VERSION 5.7 ;
BUSBITCHARS "[]" ;
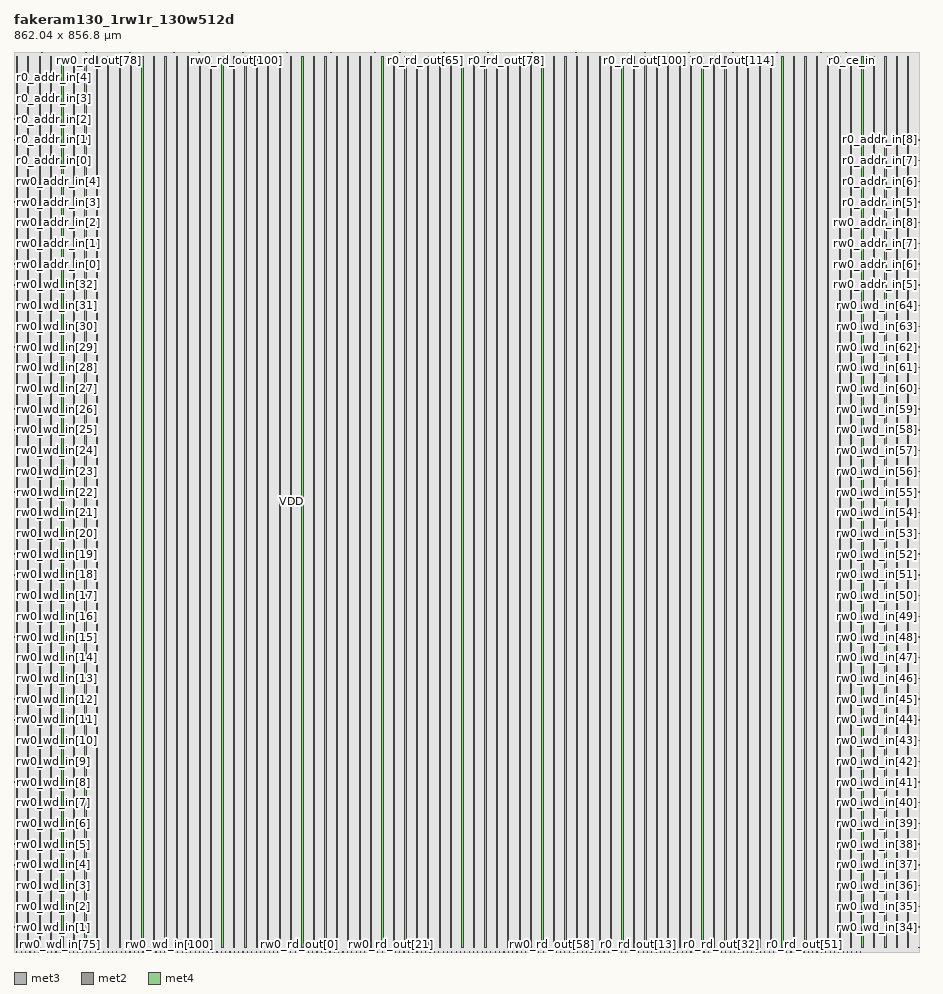
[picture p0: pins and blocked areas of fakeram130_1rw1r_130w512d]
MACRO fakeram130_1rw1r_130w512d
  FOREIGN fakeram130_1rw1r_130w512d 0 0 ;
  SYMMETRY X Y R90 ;
  SIZE 862.040 BY 856.800 ;
  CLASS BLOCK ;
  PIN rw0_wd_in[0]
    DIRECTION INPUT ;
    USE SIGNAL ;
    SHAPE ABUTMENT ;
    PORT
      LAYER met3 ;
      RECT 0.000 3.930 0.900 4.230 ;
    END
  END rw0_wd_in[0]
  PIN rw0_wd_in[1]
    DIRECTION INPUT ;
    USE SIGNAL ;
    SHAPE ABUTMENT ;
    PORT
      LAYER met3 ;
      RECT 0.000 23.650 0.900 23.950 ;
    END
  END rw0_wd_in[1]
  PIN rw0_wd_in[2]
    DIRECTION INPUT ;
    USE SIGNAL ;
    SHAPE ABUTMENT ;
    PORT
      LAYER met3 ;
      RECT 0.000 43.370 0.900 43.670 ;
    END
  END rw0_wd_in[2]
  PIN rw0_wd_in[3]
    DIRECTION INPUT ;
    USE SIGNAL ;
    SHAPE ABUTMENT ;
    PORT
      LAYER met3 ;
      RECT 0.000 63.090 0.900 63.390 ;
    END
  END rw0_wd_in[3]
  PIN rw0_wd_in[4]
    DIRECTION INPUT ;
    USE SIGNAL ;
    SHAPE ABUTMENT ;
    PORT
      LAYER met3 ;
      RECT 0.000 82.810 0.900 83.110 ;
    END
  END rw0_wd_in[4]
  PIN rw0_wd_in[5]
    DIRECTION INPUT ;
    USE SIGNAL ;
    SHAPE ABUTMENT ;
    PORT
      LAYER met3 ;
      RECT 0.000 102.530 0.900 102.830 ;
    END
  END rw0_wd_in[5]
  PIN rw0_wd_in[6]
    DIRECTION INPUT ;
    USE SIGNAL ;
    SHAPE ABUTMENT ;
    PORT
      LAYER met3 ;
      RECT 0.000 122.250 0.900 122.550 ;
    END
  END rw0_wd_in[6]
  PIN rw0_wd_in[7]
    DIRECTION INPUT ;
    USE SIGNAL ;
    SHAPE ABUTMENT ;
    PORT
      LAYER met3 ;
      RECT 0.000 141.970 0.900 142.270 ;
    END
  END rw0_wd_in[7]
  PIN rw0_wd_in[8]
    DIRECTION INPUT ;
    USE SIGNAL ;
    SHAPE ABUTMENT ;
    PORT
      LAYER met3 ;
      RECT 0.000 161.690 0.900 161.990 ;
    END
  END rw0_wd_in[8]
  PIN rw0_wd_in[9]
    DIRECTION INPUT ;
    USE SIGNAL ;
    SHAPE ABUTMENT ;
    PORT
      LAYER met3 ;
      RECT 0.000 181.410 0.900 181.710 ;
    END
  END rw0_wd_in[9]
  PIN rw0_wd_in[10]
    DIRECTION INPUT ;
    USE SIGNAL ;
    SHAPE ABUTMENT ;
    PORT
      LAYER met3 ;
      RECT 0.000 201.130 0.900 201.430 ;
    END
  END rw0_wd_in[10]
  PIN rw0_wd_in[11]
    DIRECTION INPUT ;
    USE SIGNAL ;
    SHAPE ABUTMENT ;
    PORT
      LAYER met3 ;
      RECT 0.000 220.850 0.900 221.150 ;
    END
  END rw0_wd_in[11]
  PIN rw0_wd_in[12]
    DIRECTION INPUT ;
    USE SIGNAL ;
    SHAPE ABUTMENT ;
    PORT
      LAYER met3 ;
      RECT 0.000 240.570 0.900 240.870 ;
    END
  END rw0_wd_in[12]
  PIN rw0_wd_in[13]
    DIRECTION INPUT ;
    USE SIGNAL ;
    SHAPE ABUTMENT ;
    PORT
      LAYER met3 ;
      RECT 0.000 260.290 0.900 260.590 ;
    END
  END rw0_wd_in[13]
  PIN rw0_wd_in[14]
    DIRECTION INPUT ;
    USE SIGNAL ;
    SHAPE ABUTMENT ;
    PORT
      LAYER met3 ;
      RECT 0.000 280.010 0.900 280.310 ;
    END
  END rw0_wd_in[14]
  PIN rw0_wd_in[15]
    DIRECTION INPUT ;
    USE SIGNAL ;
    SHAPE ABUTMENT ;
    PORT
      LAYER met3 ;
      RECT 0.000 299.730 0.900 300.030 ;
    END
  END rw0_wd_in[15]
  PIN rw0_wd_in[16]
    DIRECTION INPUT ;
    USE SIGNAL ;
    SHAPE ABUTMENT ;
    PORT
      LAYER met3 ;
      RECT 0.000 319.450 0.900 319.750 ;
    END
  END rw0_wd_in[16]
  PIN rw0_wd_in[17]
    DIRECTION INPUT ;
    USE SIGNAL ;
    SHAPE ABUTMENT ;
    PORT
      LAYER met3 ;
      RECT 0.000 339.170 0.900 339.470 ;
    END
  END rw0_wd_in[17]
  PIN rw0_wd_in[18]
    DIRECTION INPUT ;
    USE SIGNAL ;
    SHAPE ABUTMENT ;
    PORT
      LAYER met3 ;
      RECT 0.000 358.890 0.900 359.190 ;
    END
  END rw0_wd_in[18]
  PIN rw0_wd_in[19]
    DIRECTION INPUT ;
    USE SIGNAL ;
    SHAPE ABUTMENT ;
    PORT
      LAYER met3 ;
      RECT 0.000 378.610 0.900 378.910 ;
    END
  END rw0_wd_in[19]
  PIN rw0_wd_in[20]
    DIRECTION INPUT ;
    USE SIGNAL ;
    SHAPE ABUTMENT ;
    PORT
      LAYER met3 ;
      RECT 0.000 398.330 0.900 398.630 ;
    END
  END rw0_wd_in[20]
  PIN rw0_wd_in[21]
    DIRECTION INPUT ;
    USE SIGNAL ;
    SHAPE ABUTMENT ;
    PORT
      LAYER met3 ;
      RECT 0.000 418.050 0.900 418.350 ;
    END
  END rw0_wd_in[21]
  PIN rw0_wd_in[22]
    DIRECTION INPUT ;
    USE SIGNAL ;
    SHAPE ABUTMENT ;
    PORT
      LAYER met3 ;
      RECT 0.000 437.770 0.900 438.070 ;
    END
  END rw0_wd_in[22]
  PIN rw0_wd_in[23]
    DIRECTION INPUT ;
    USE SIGNAL ;
    SHAPE ABUTMENT ;
    PORT
      LAYER met3 ;
      RECT 0.000 457.490 0.900 457.790 ;
    END
  END rw0_wd_in[23]
  PIN rw0_wd_in[24]
    DIRECTION INPUT ;
    USE SIGNAL ;
    SHAPE ABUTMENT ;
    PORT
      LAYER met3 ;
      RECT 0.000 477.210 0.900 477.510 ;
    END
  END rw0_wd_in[24]
  PIN rw0_wd_in[25]
    DIRECTION INPUT ;
    USE SIGNAL ;
    SHAPE ABUTMENT ;
    PORT
      LAYER met3 ;
      RECT 0.000 496.930 0.900 497.230 ;
    END
  END rw0_wd_in[25]
  PIN rw0_wd_in[26]
    DIRECTION INPUT ;
    USE SIGNAL ;
    SHAPE ABUTMENT ;
    PORT
      LAYER met3 ;
      RECT 0.000 516.650 0.900 516.950 ;
    END
  END rw0_wd_in[26]
  PIN rw0_wd_in[27]
    DIRECTION INPUT ;
    USE SIGNAL ;
    SHAPE ABUTMENT ;
    PORT
      LAYER met3 ;
      RECT 0.000 536.370 0.900 536.670 ;
    END
  END rw0_wd_in[27]
  PIN rw0_wd_in[28]
    DIRECTION INPUT ;
    USE SIGNAL ;
    SHAPE ABUTMENT ;
    PORT
      LAYER met3 ;
      RECT 0.000 556.090 0.900 556.390 ;
    END
  END rw0_wd_in[28]
  PIN rw0_wd_in[29]
    DIRECTION INPUT ;
    USE SIGNAL ;
    SHAPE ABUTMENT ;
    PORT
      LAYER met3 ;
      RECT 0.000 575.810 0.900 576.110 ;
    END
  END rw0_wd_in[29]
  PIN rw0_wd_in[30]
    DIRECTION INPUT ;
    USE SIGNAL ;
    SHAPE ABUTMENT ;
    PORT
      LAYER met3 ;
      RECT 0.000 595.530 0.900 595.830 ;
    END
  END rw0_wd_in[30]
  PIN rw0_wd_in[31]
    DIRECTION INPUT ;
    USE SIGNAL ;
    SHAPE ABUTMENT ;
    PORT
      LAYER met3 ;
      RECT 0.000 615.250 0.900 615.550 ;
    END
  END rw0_wd_in[31]
  PIN rw0_wd_in[32]
    DIRECTION INPUT ;
    USE SIGNAL ;
    SHAPE ABUTMENT ;
    PORT
      LAYER met3 ;
      RECT 0.000 634.970 0.900 635.270 ;
    END
  END rw0_wd_in[32]
  PIN rw0_wd_in[33]
    DIRECTION INPUT ;
    USE SIGNAL ;
    SHAPE ABUTMENT ;
    PORT
      LAYER met3 ;
      RECT 861.140 3.930 862.040 4.230 ;
    END
  END rw0_wd_in[33]
  PIN rw0_wd_in[34]
    DIRECTION INPUT ;
    USE SIGNAL ;
    SHAPE ABUTMENT ;
    PORT
      LAYER met3 ;
      RECT 861.140 23.650 862.040 23.950 ;
    END
  END rw0_wd_in[34]
  PIN rw0_wd_in[35]
    DIRECTION INPUT ;
    USE SIGNAL ;
    SHAPE ABUTMENT ;
    PORT
      LAYER met3 ;
      RECT 861.140 43.370 862.040 43.670 ;
    END
  END rw0_wd_in[35]
  PIN rw0_wd_in[36]
    DIRECTION INPUT ;
    USE SIGNAL ;
    SHAPE ABUTMENT ;
    PORT
      LAYER met3 ;
      RECT 861.140 63.090 862.040 63.390 ;
    END
  END rw0_wd_in[36]
  PIN rw0_wd_in[37]
    DIRECTION INPUT ;
    USE SIGNAL ;
    SHAPE ABUTMENT ;
    PORT
      LAYER met3 ;
      RECT 861.140 82.810 862.040 83.110 ;
    END
  END rw0_wd_in[37]
  PIN rw0_wd_in[38]
    DIRECTION INPUT ;
    USE SIGNAL ;
    SHAPE ABUTMENT ;
    PORT
      LAYER met3 ;
      RECT 861.140 102.530 862.040 102.830 ;
    END
  END rw0_wd_in[38]
  PIN rw0_wd_in[39]
    DIRECTION INPUT ;
    USE SIGNAL ;
    SHAPE ABUTMENT ;
    PORT
      LAYER met3 ;
      RECT 861.140 122.250 862.040 122.550 ;
    END
  END rw0_wd_in[39]
  PIN rw0_wd_in[40]
    DIRECTION INPUT ;
    USE SIGNAL ;
    SHAPE ABUTMENT ;
    PORT
      LAYER met3 ;
      RECT 861.140 141.970 862.040 142.270 ;
    END
  END rw0_wd_in[40]
  PIN rw0_wd_in[41]
    DIRECTION INPUT ;
    USE SIGNAL ;
    SHAPE ABUTMENT ;
    PORT
      LAYER met3 ;
      RECT 861.140 161.690 862.040 161.990 ;
    END
  END rw0_wd_in[41]
  PIN rw0_wd_in[42]
    DIRECTION INPUT ;
    USE SIGNAL ;
    SHAPE ABUTMENT ;
    PORT
      LAYER met3 ;
      RECT 861.140 181.410 862.040 181.710 ;
    END
  END rw0_wd_in[42]
  PIN rw0_wd_in[43]
    DIRECTION INPUT ;
    USE SIGNAL ;
    SHAPE ABUTMENT ;
    PORT
      LAYER met3 ;
      RECT 861.140 201.130 862.040 201.430 ;
    END
  END rw0_wd_in[43]
  PIN rw0_wd_in[44]
    DIRECTION INPUT ;
    USE SIGNAL ;
    SHAPE ABUTMENT ;
    PORT
      LAYER met3 ;
      RECT 861.140 220.850 862.040 221.150 ;
    END
  END rw0_wd_in[44]
  PIN rw0_wd_in[45]
    DIRECTION INPUT ;
    USE SIGNAL ;
    SHAPE ABUTMENT ;
    PORT
      LAYER met3 ;
      RECT 861.140 240.570 862.040 240.870 ;
    END
  END rw0_wd_in[45]
  PIN rw0_wd_in[46]
    DIRECTION INPUT ;
    USE SIGNAL ;
    SHAPE ABUTMENT ;
    PORT
      LAYER met3 ;
      RECT 861.140 260.290 862.040 260.590 ;
    END
  END rw0_wd_in[46]
  PIN rw0_wd_in[47]
    DIRECTION INPUT ;
    USE SIGNAL ;
    SHAPE ABUTMENT ;
    PORT
      LAYER met3 ;
      RECT 861.140 280.010 862.040 280.310 ;
    END
  END rw0_wd_in[47]
  PIN rw0_wd_in[48]
    DIRECTION INPUT ;
    USE SIGNAL ;
    SHAPE ABUTMENT ;
    PORT
      LAYER met3 ;
      RECT 861.140 299.730 862.040 300.030 ;
    END
  END rw0_wd_in[48]
  PIN rw0_wd_in[49]
    DIRECTION INPUT ;
    USE SIGNAL ;
    SHAPE ABUTMENT ;
    PORT
      LAYER met3 ;
      RECT 861.140 319.450 862.040 319.750 ;
    END
  END rw0_wd_in[49]
  PIN rw0_wd_in[50]
    DIRECTION INPUT ;
    USE SIGNAL ;
    SHAPE ABUTMENT ;
    PORT
      LAYER met3 ;
      RECT 861.140 339.170 862.040 339.470 ;
    END
  END rw0_wd_in[50]
  PIN rw0_wd_in[51]
    DIRECTION INPUT ;
    USE SIGNAL ;
    SHAPE ABUTMENT ;
    PORT
      LAYER met3 ;
      RECT 861.140 358.890 862.040 359.190 ;
    END
  END rw0_wd_in[51]
  PIN rw0_wd_in[52]
    DIRECTION INPUT ;
    USE SIGNAL ;
    SHAPE ABUTMENT ;
    PORT
      LAYER met3 ;
      RECT 861.140 378.610 862.040 378.910 ;
    END
  END rw0_wd_in[52]
  PIN rw0_wd_in[53]
    DIRECTION INPUT ;
    USE SIGNAL ;
    SHAPE ABUTMENT ;
    PORT
      LAYER met3 ;
      RECT 861.140 398.330 862.040 398.630 ;
    END
  END rw0_wd_in[53]
  PIN rw0_wd_in[54]
    DIRECTION INPUT ;
    USE SIGNAL ;
    SHAPE ABUTMENT ;
    PORT
      LAYER met3 ;
      RECT 861.140 418.050 862.040 418.350 ;
    END
  END rw0_wd_in[54]
  PIN rw0_wd_in[55]
    DIRECTION INPUT ;
    USE SIGNAL ;
    SHAPE ABUTMENT ;
    PORT
      LAYER met3 ;
      RECT 861.140 437.770 862.040 438.070 ;
    END
  END rw0_wd_in[55]
  PIN rw0_wd_in[56]
    DIRECTION INPUT ;
    USE SIGNAL ;
    SHAPE ABUTMENT ;
    PORT
      LAYER met3 ;
      RECT 861.140 457.490 862.040 457.790 ;
    END
  END rw0_wd_in[56]
  PIN rw0_wd_in[57]
    DIRECTION INPUT ;
    USE SIGNAL ;
    SHAPE ABUTMENT ;
    PORT
      LAYER met3 ;
      RECT 861.140 477.210 862.040 477.510 ;
    END
  END rw0_wd_in[57]
  PIN rw0_wd_in[58]
    DIRECTION INPUT ;
    USE SIGNAL ;
    SHAPE ABUTMENT ;
    PORT
      LAYER met3 ;
      RECT 861.140 496.930 862.040 497.230 ;
    END
  END rw0_wd_in[58]
  PIN rw0_wd_in[59]
    DIRECTION INPUT ;
    USE SIGNAL ;
    SHAPE ABUTMENT ;
    PORT
      LAYER met3 ;
      RECT 861.140 516.650 862.040 516.950 ;
    END
  END rw0_wd_in[59]
  PIN rw0_wd_in[60]
    DIRECTION INPUT ;
    USE SIGNAL ;
    SHAPE ABUTMENT ;
    PORT
      LAYER met3 ;
      RECT 861.140 536.370 862.040 536.670 ;
    END
  END rw0_wd_in[60]
  PIN rw0_wd_in[61]
    DIRECTION INPUT ;
    USE SIGNAL ;
    SHAPE ABUTMENT ;
    PORT
      LAYER met3 ;
      RECT 861.140 556.090 862.040 556.390 ;
    END
  END rw0_wd_in[61]
  PIN rw0_wd_in[62]
    DIRECTION INPUT ;
    USE SIGNAL ;
    SHAPE ABUTMENT ;
    PORT
      LAYER met3 ;
      RECT 861.140 575.810 862.040 576.110 ;
    END
  END rw0_wd_in[62]
  PIN rw0_wd_in[63]
    DIRECTION INPUT ;
    USE SIGNAL ;
    SHAPE ABUTMENT ;
    PORT
      LAYER met3 ;
      RECT 861.140 595.530 862.040 595.830 ;
    END
  END rw0_wd_in[63]
  PIN rw0_wd_in[64]
    DIRECTION INPUT ;
    USE SIGNAL ;
    SHAPE ABUTMENT ;
    PORT
      LAYER met3 ;
      RECT 861.140 615.250 862.040 615.550 ;
    END
  END rw0_wd_in[64]
  PIN rw0_wd_in[65]
    DIRECTION OUTPUT ;
    USE SIGNAL ;
    SHAPE ABUTMENT ;
    PORT
      LAYER met2 ;
      RECT 2.690 0.000 2.830 0.420 ;
    END
  END rw0_wd_in[65]
  PIN rw0_wd_in[66]
    DIRECTION OUTPUT ;
    USE SIGNAL ;
    SHAPE ABUTMENT ;
    PORT
      LAYER met2 ;
      RECT 6.830 0.000 6.970 0.420 ;
    END
  END rw0_wd_in[66]
  PIN rw0_wd_in[67]
    DIRECTION OUTPUT ;
    USE SIGNAL ;
    SHAPE ABUTMENT ;
    PORT
      LAYER met2 ;
      RECT 10.970 0.000 11.110 0.420 ;
    END
  END rw0_wd_in[67]
  PIN rw0_wd_in[68]
    DIRECTION OUTPUT ;
    USE SIGNAL ;
    SHAPE ABUTMENT ;
    PORT
      LAYER met2 ;
      RECT 15.110 0.000 15.250 0.420 ;
    END
  END rw0_wd_in[68]
  PIN rw0_wd_in[69]
    DIRECTION OUTPUT ;
    USE SIGNAL ;
    SHAPE ABUTMENT ;
    PORT
      LAYER met2 ;
      RECT 19.250 0.000 19.390 0.420 ;
    END
  END rw0_wd_in[69]
  PIN rw0_wd_in[70]
    DIRECTION OUTPUT ;
    USE SIGNAL ;
    SHAPE ABUTMENT ;
    PORT
      LAYER met2 ;
      RECT 23.390 0.000 23.530 0.420 ;
    END
  END rw0_wd_in[70]
  PIN rw0_wd_in[71]
    DIRECTION OUTPUT ;
    USE SIGNAL ;
    SHAPE ABUTMENT ;
    PORT
      LAYER met2 ;
      RECT 27.530 0.000 27.670 0.420 ;
    END
  END rw0_wd_in[71]
  PIN rw0_wd_in[72]
    DIRECTION OUTPUT ;
    USE SIGNAL ;
    SHAPE ABUTMENT ;
    PORT
      LAYER met2 ;
      RECT 31.670 0.000 31.810 0.420 ;
    END
  END rw0_wd_in[72]
  PIN rw0_wd_in[73]
    DIRECTION OUTPUT ;
    USE SIGNAL ;
    SHAPE ABUTMENT ;
    PORT
      LAYER met2 ;
      RECT 35.810 0.000 35.950 0.420 ;
    END
  END rw0_wd_in[73]
  PIN rw0_wd_in[74]
    DIRECTION OUTPUT ;
    USE SIGNAL ;
    SHAPE ABUTMENT ;
    PORT
      LAYER met2 ;
      RECT 39.950 0.000 40.090 0.420 ;
    END
  END rw0_wd_in[74]
  PIN rw0_wd_in[75]
    DIRECTION OUTPUT ;
    USE SIGNAL ;
    SHAPE ABUTMENT ;
    PORT
      LAYER met2 ;
      RECT 44.090 0.000 44.230 0.420 ;
    END
  END rw0_wd_in[75]
  PIN rw0_wd_in[76]
    DIRECTION OUTPUT ;
    USE SIGNAL ;
    SHAPE ABUTMENT ;
    PORT
      LAYER met2 ;
      RECT 48.230 0.000 48.370 0.420 ;
    END
  END rw0_wd_in[76]
  PIN rw0_wd_in[77]
    DIRECTION OUTPUT ;
    USE SIGNAL ;
    SHAPE ABUTMENT ;
    PORT
      LAYER met2 ;
      RECT 52.370 0.000 52.510 0.420 ;
    END
  END rw0_wd_in[77]
  PIN rw0_wd_in[78]
    DIRECTION OUTPUT ;
    USE SIGNAL ;
    SHAPE ABUTMENT ;
    PORT
      LAYER met2 ;
      RECT 56.510 0.000 56.650 0.420 ;
    END
  END rw0_wd_in[78]
  PIN rw0_wd_in[79]
    DIRECTION OUTPUT ;
    USE SIGNAL ;
    SHAPE ABUTMENT ;
    PORT
      LAYER met2 ;
      RECT 60.650 0.000 60.790 0.420 ;
    END
  END rw0_wd_in[79]
  PIN rw0_wd_in[80]
    DIRECTION OUTPUT ;
    USE SIGNAL ;
    SHAPE ABUTMENT ;
    PORT
      LAYER met2 ;
      RECT 64.790 0.000 64.930 0.420 ;
    END
  END rw0_wd_in[80]
  PIN rw0_wd_in[81]
    DIRECTION OUTPUT ;
    USE SIGNAL ;
    SHAPE ABUTMENT ;
    PORT
      LAYER met2 ;
      RECT 68.930 0.000 69.070 0.420 ;
    END
  END rw0_wd_in[81]
  PIN rw0_wd_in[82]
    DIRECTION OUTPUT ;
    USE SIGNAL ;
    SHAPE ABUTMENT ;
    PORT
      LAYER met2 ;
      RECT 73.070 0.000 73.210 0.420 ;
    END
  END rw0_wd_in[82]
  PIN rw0_wd_in[83]
    DIRECTION OUTPUT ;
    USE SIGNAL ;
    SHAPE ABUTMENT ;
    PORT
      LAYER met2 ;
      RECT 77.210 0.000 77.350 0.420 ;
    END
  END rw0_wd_in[83]
  PIN rw0_wd_in[84]
    DIRECTION OUTPUT ;
    USE SIGNAL ;
    SHAPE ABUTMENT ;
    PORT
      LAYER met2 ;
      RECT 81.350 0.000 81.490 0.420 ;
    END
  END rw0_wd_in[84]
  PIN rw0_wd_in[85]
    DIRECTION OUTPUT ;
    USE SIGNAL ;
    SHAPE ABUTMENT ;
    PORT
      LAYER met2 ;
      RECT 85.490 0.000 85.630 0.420 ;
    END
  END rw0_wd_in[85]
  PIN rw0_wd_in[86]
    DIRECTION OUTPUT ;
    USE SIGNAL ;
    SHAPE ABUTMENT ;
    PORT
      LAYER met2 ;
      RECT 89.630 0.000 89.770 0.420 ;
    END
  END rw0_wd_in[86]
  PIN rw0_wd_in[87]
    DIRECTION OUTPUT ;
    USE SIGNAL ;
    SHAPE ABUTMENT ;
    PORT
      LAYER met2 ;
      RECT 93.770 0.000 93.910 0.420 ;
    END
  END rw0_wd_in[87]
  PIN rw0_wd_in[88]
    DIRECTION OUTPUT ;
    USE SIGNAL ;
    SHAPE ABUTMENT ;
    PORT
      LAYER met2 ;
      RECT 97.910 0.000 98.050 0.420 ;
    END
  END rw0_wd_in[88]
  PIN rw0_wd_in[89]
    DIRECTION OUTPUT ;
    USE SIGNAL ;
    SHAPE ABUTMENT ;
    PORT
      LAYER met2 ;
      RECT 102.050 0.000 102.190 0.420 ;
    END
  END rw0_wd_in[89]
  PIN rw0_wd_in[90]
    DIRECTION OUTPUT ;
    USE SIGNAL ;
    SHAPE ABUTMENT ;
    PORT
      LAYER met2 ;
      RECT 106.190 0.000 106.330 0.420 ;
    END
  END rw0_wd_in[90]
  PIN rw0_wd_in[91]
    DIRECTION OUTPUT ;
    USE SIGNAL ;
    SHAPE ABUTMENT ;
    PORT
      LAYER met2 ;
      RECT 110.330 0.000 110.470 0.420 ;
    END
  END rw0_wd_in[91]
  PIN rw0_wd_in[92]
    DIRECTION OUTPUT ;
    USE SIGNAL ;
    SHAPE ABUTMENT ;
    PORT
      LAYER met2 ;
      RECT 114.470 0.000 114.610 0.420 ;
    END
  END rw0_wd_in[92]
  PIN rw0_wd_in[93]
    DIRECTION OUTPUT ;
    USE SIGNAL ;
    SHAPE ABUTMENT ;
    PORT
      LAYER met2 ;
      RECT 118.610 0.000 118.750 0.420 ;
    END
  END rw0_wd_in[93]
  PIN rw0_wd_in[94]
    DIRECTION OUTPUT ;
    USE SIGNAL ;
    SHAPE ABUTMENT ;
    PORT
      LAYER met2 ;
      RECT 122.750 0.000 122.890 0.420 ;
    END
  END rw0_wd_in[94]
  PIN rw0_wd_in[95]
    DIRECTION OUTPUT ;
    USE SIGNAL ;
    SHAPE ABUTMENT ;
    PORT
      LAYER met2 ;
      RECT 126.890 0.000 127.030 0.420 ;
    END
  END rw0_wd_in[95]
  PIN rw0_wd_in[96]
    DIRECTION OUTPUT ;
    USE SIGNAL ;
    SHAPE ABUTMENT ;
    PORT
      LAYER met2 ;
      RECT 131.030 0.000 131.170 0.420 ;
    END
  END rw0_wd_in[96]
  PIN rw0_wd_in[97]
    DIRECTION OUTPUT ;
    USE SIGNAL ;
    SHAPE ABUTMENT ;
    PORT
      LAYER met2 ;
      RECT 135.170 0.000 135.310 0.420 ;
    END
  END rw0_wd_in[97]
  PIN rw0_wd_in[98]
    DIRECTION OUTPUT ;
    USE SIGNAL ;
    SHAPE ABUTMENT ;
    PORT
      LAYER met2 ;
      RECT 139.310 0.000 139.450 0.420 ;
    END
  END rw0_wd_in[98]
  PIN rw0_wd_in[99]
    DIRECTION OUTPUT ;
    USE SIGNAL ;
    SHAPE ABUTMENT ;
    PORT
      LAYER met2 ;
      RECT 143.450 0.000 143.590 0.420 ;
    END
  END rw0_wd_in[99]
  PIN rw0_wd_in[100]
    DIRECTION OUTPUT ;
    USE SIGNAL ;
    SHAPE ABUTMENT ;
    PORT
      LAYER met2 ;
      RECT 147.590 0.000 147.730 0.420 ;
    END
  END rw0_wd_in[100]
  PIN rw0_wd_in[101]
    DIRECTION OUTPUT ;
    USE SIGNAL ;
    SHAPE ABUTMENT ;
    PORT
      LAYER met2 ;
      RECT 151.730 0.000 151.870 0.420 ;
    END
  END rw0_wd_in[101]
  PIN rw0_wd_in[102]
    DIRECTION OUTPUT ;
    USE SIGNAL ;
    SHAPE ABUTMENT ;
    PORT
      LAYER met2 ;
      RECT 155.870 0.000 156.010 0.420 ;
    END
  END rw0_wd_in[102]
  PIN rw0_wd_in[103]
    DIRECTION OUTPUT ;
    USE SIGNAL ;
    SHAPE ABUTMENT ;
    PORT
      LAYER met2 ;
      RECT 160.010 0.000 160.150 0.420 ;
    END
  END rw0_wd_in[103]
  PIN rw0_wd_in[104]
    DIRECTION OUTPUT ;
    USE SIGNAL ;
    SHAPE ABUTMENT ;
    PORT
      LAYER met2 ;
      RECT 164.150 0.000 164.290 0.420 ;
    END
  END rw0_wd_in[104]
  PIN rw0_wd_in[105]
    DIRECTION OUTPUT ;
    USE SIGNAL ;
    SHAPE ABUTMENT ;
    PORT
      LAYER met2 ;
      RECT 168.290 0.000 168.430 0.420 ;
    END
  END rw0_wd_in[105]
  PIN rw0_wd_in[106]
    DIRECTION OUTPUT ;
    USE SIGNAL ;
    SHAPE ABUTMENT ;
    PORT
      LAYER met2 ;
      RECT 172.430 0.000 172.570 0.420 ;
    END
  END rw0_wd_in[106]
  PIN rw0_wd_in[107]
    DIRECTION OUTPUT ;
    USE SIGNAL ;
    SHAPE ABUTMENT ;
    PORT
      LAYER met2 ;
      RECT 176.570 0.000 176.710 0.420 ;
    END
  END rw0_wd_in[107]
  PIN rw0_wd_in[108]
    DIRECTION OUTPUT ;
    USE SIGNAL ;
    SHAPE ABUTMENT ;
    PORT
      LAYER met2 ;
      RECT 180.710 0.000 180.850 0.420 ;
    END
  END rw0_wd_in[108]
  PIN rw0_wd_in[109]
    DIRECTION OUTPUT ;
    USE SIGNAL ;
    SHAPE ABUTMENT ;
    PORT
      LAYER met2 ;
      RECT 184.850 0.000 184.990 0.420 ;
    END
  END rw0_wd_in[109]
  PIN rw0_wd_in[110]
    DIRECTION OUTPUT ;
    USE SIGNAL ;
    SHAPE ABUTMENT ;
    PORT
      LAYER met2 ;
      RECT 188.990 0.000 189.130 0.420 ;
    END
  END rw0_wd_in[110]
  PIN rw0_wd_in[111]
    DIRECTION OUTPUT ;
    USE SIGNAL ;
    SHAPE ABUTMENT ;
    PORT
      LAYER met2 ;
      RECT 193.130 0.000 193.270 0.420 ;
    END
  END rw0_wd_in[111]
  PIN rw0_wd_in[112]
    DIRECTION OUTPUT ;
    USE SIGNAL ;
    SHAPE ABUTMENT ;
    PORT
      LAYER met2 ;
      RECT 197.270 0.000 197.410 0.420 ;
    END
  END rw0_wd_in[112]
  PIN rw0_wd_in[113]
    DIRECTION OUTPUT ;
    USE SIGNAL ;
    SHAPE ABUTMENT ;
    PORT
      LAYER met2 ;
      RECT 201.410 0.000 201.550 0.420 ;
    END
  END rw0_wd_in[113]
  PIN rw0_wd_in[114]
    DIRECTION OUTPUT ;
    USE SIGNAL ;
    SHAPE ABUTMENT ;
    PORT
      LAYER met2 ;
      RECT 205.550 0.000 205.690 0.420 ;
    END
  END rw0_wd_in[114]
  PIN rw0_wd_in[115]
    DIRECTION OUTPUT ;
    USE SIGNAL ;
    SHAPE ABUTMENT ;
    PORT
      LAYER met2 ;
      RECT 209.690 0.000 209.830 0.420 ;
    END
  END rw0_wd_in[115]
  PIN rw0_wd_in[116]
    DIRECTION OUTPUT ;
    USE SIGNAL ;
    SHAPE ABUTMENT ;
    PORT
      LAYER met2 ;
      RECT 213.830 0.000 213.970 0.420 ;
    END
  END rw0_wd_in[116]
  PIN rw0_wd_in[117]
    DIRECTION OUTPUT ;
    USE SIGNAL ;
    SHAPE ABUTMENT ;
    PORT
      LAYER met2 ;
      RECT 217.970 0.000 218.110 0.420 ;
    END
  END rw0_wd_in[117]
  PIN rw0_wd_in[118]
    DIRECTION OUTPUT ;
    USE SIGNAL ;
    SHAPE ABUTMENT ;
    PORT
      LAYER met2 ;
      RECT 222.110 0.000 222.250 0.420 ;
    END
  END rw0_wd_in[118]
  PIN rw0_wd_in[119]
    DIRECTION OUTPUT ;
    USE SIGNAL ;
    SHAPE ABUTMENT ;
    PORT
      LAYER met2 ;
      RECT 226.250 0.000 226.390 0.420 ;
    END
  END rw0_wd_in[119]
  PIN rw0_wd_in[120]
    DIRECTION OUTPUT ;
    USE SIGNAL ;
    SHAPE ABUTMENT ;
    PORT
      LAYER met2 ;
      RECT 230.390 0.000 230.530 0.420 ;
    END
  END rw0_wd_in[120]
  PIN rw0_wd_in[121]
    DIRECTION OUTPUT ;
    USE SIGNAL ;
    SHAPE ABUTMENT ;
    PORT
      LAYER met2 ;
      RECT 234.530 0.000 234.670 0.420 ;
    END
  END rw0_wd_in[121]
  PIN rw0_wd_in[122]
    DIRECTION OUTPUT ;
    USE SIGNAL ;
    SHAPE ABUTMENT ;
    PORT
      LAYER met2 ;
      RECT 238.670 0.000 238.810 0.420 ;
    END
  END rw0_wd_in[122]
  PIN rw0_wd_in[123]
    DIRECTION OUTPUT ;
    USE SIGNAL ;
    SHAPE ABUTMENT ;
    PORT
      LAYER met2 ;
      RECT 242.810 0.000 242.950 0.420 ;
    END
  END rw0_wd_in[123]
  PIN rw0_wd_in[124]
    DIRECTION OUTPUT ;
    USE SIGNAL ;
    SHAPE ABUTMENT ;
    PORT
      LAYER met2 ;
      RECT 246.950 0.000 247.090 0.420 ;
    END
  END rw0_wd_in[124]
  PIN rw0_wd_in[125]
    DIRECTION OUTPUT ;
    USE SIGNAL ;
    SHAPE ABUTMENT ;
    PORT
      LAYER met2 ;
      RECT 251.090 0.000 251.230 0.420 ;
    END
  END rw0_wd_in[125]
  PIN rw0_wd_in[126]
    DIRECTION OUTPUT ;
    USE SIGNAL ;
    SHAPE ABUTMENT ;
    PORT
      LAYER met2 ;
      RECT 255.230 0.000 255.370 0.420 ;
    END
  END rw0_wd_in[126]
  PIN rw0_wd_in[127]
    DIRECTION OUTPUT ;
    USE SIGNAL ;
    SHAPE ABUTMENT ;
    PORT
      LAYER met2 ;
      RECT 259.370 0.000 259.510 0.420 ;
    END
  END rw0_wd_in[127]
  PIN rw0_wd_in[128]
    DIRECTION OUTPUT ;
    USE SIGNAL ;
    SHAPE ABUTMENT ;
    PORT
      LAYER met2 ;
      RECT 263.510 0.000 263.650 0.420 ;
    END
  END rw0_wd_in[128]
  PIN rw0_wd_in[129]
    DIRECTION OUTPUT ;
    USE SIGNAL ;
    SHAPE ABUTMENT ;
    PORT
      LAYER met2 ;
      RECT 267.650 0.000 267.790 0.420 ;
    END
  END rw0_wd_in[129]
  PIN rw0_rd_out[0]
    DIRECTION OUTPUT ;
    USE SIGNAL ;
    SHAPE ABUTMENT ;
    PORT
      LAYER met2 ;
      RECT 271.790 0.000 271.930 0.420 ;
    END
  END rw0_rd_out[0]
  PIN rw0_rd_out[1]
    DIRECTION OUTPUT ;
    USE SIGNAL ;
    SHAPE ABUTMENT ;
    PORT
      LAYER met2 ;
      RECT 275.930 0.000 276.070 0.420 ;
    END
  END rw0_rd_out[1]
  PIN rw0_rd_out[2]
    DIRECTION OUTPUT ;
    USE SIGNAL ;
    SHAPE ABUTMENT ;
    PORT
      LAYER met2 ;
      RECT 280.070 0.000 280.210 0.420 ;
    END
  END rw0_rd_out[2]
  PIN rw0_rd_out[3]
    DIRECTION OUTPUT ;
    USE SIGNAL ;
    SHAPE ABUTMENT ;
    PORT
      LAYER met2 ;
      RECT 284.210 0.000 284.350 0.420 ;
    END
  END rw0_rd_out[3]
  PIN rw0_rd_out[4]
    DIRECTION OUTPUT ;
    USE SIGNAL ;
    SHAPE ABUTMENT ;
    PORT
      LAYER met2 ;
      RECT 288.350 0.000 288.490 0.420 ;
    END
  END rw0_rd_out[4]
  PIN rw0_rd_out[5]
    DIRECTION OUTPUT ;
    USE SIGNAL ;
    SHAPE ABUTMENT ;
    PORT
      LAYER met2 ;
      RECT 292.490 0.000 292.630 0.420 ;
    END
  END rw0_rd_out[5]
  PIN rw0_rd_out[6]
    DIRECTION OUTPUT ;
    USE SIGNAL ;
    SHAPE ABUTMENT ;
    PORT
      LAYER met2 ;
      RECT 296.630 0.000 296.770 0.420 ;
    END
  END rw0_rd_out[6]
  PIN rw0_rd_out[7]
    DIRECTION OUTPUT ;
    USE SIGNAL ;
    SHAPE ABUTMENT ;
    PORT
      LAYER met2 ;
      RECT 300.770 0.000 300.910 0.420 ;
    END
  END rw0_rd_out[7]
  PIN rw0_rd_out[8]
    DIRECTION OUTPUT ;
    USE SIGNAL ;
    SHAPE ABUTMENT ;
    PORT
      LAYER met2 ;
      RECT 304.910 0.000 305.050 0.420 ;
    END
  END rw0_rd_out[8]
  PIN rw0_rd_out[9]
    DIRECTION OUTPUT ;
    USE SIGNAL ;
    SHAPE ABUTMENT ;
    PORT
      LAYER met2 ;
      RECT 309.050 0.000 309.190 0.420 ;
    END
  END rw0_rd_out[9]
  PIN rw0_rd_out[10]
    DIRECTION OUTPUT ;
    USE SIGNAL ;
    SHAPE ABUTMENT ;
    PORT
      LAYER met2 ;
      RECT 313.190 0.000 313.330 0.420 ;
    END
  END rw0_rd_out[10]
  PIN rw0_rd_out[11]
    DIRECTION OUTPUT ;
    USE SIGNAL ;
    SHAPE ABUTMENT ;
    PORT
      LAYER met2 ;
      RECT 317.330 0.000 317.470 0.420 ;
    END
  END rw0_rd_out[11]
  PIN rw0_rd_out[12]
    DIRECTION OUTPUT ;
    USE SIGNAL ;
    SHAPE ABUTMENT ;
    PORT
      LAYER met2 ;
      RECT 321.470 0.000 321.610 0.420 ;
    END
  END rw0_rd_out[12]
  PIN rw0_rd_out[13]
    DIRECTION OUTPUT ;
    USE SIGNAL ;
    SHAPE ABUTMENT ;
    PORT
      LAYER met2 ;
      RECT 325.610 0.000 325.750 0.420 ;
    END
  END rw0_rd_out[13]
  PIN rw0_rd_out[14]
    DIRECTION OUTPUT ;
    USE SIGNAL ;
    SHAPE ABUTMENT ;
    PORT
      LAYER met2 ;
      RECT 329.750 0.000 329.890 0.420 ;
    END
  END rw0_rd_out[14]
  PIN rw0_rd_out[15]
    DIRECTION OUTPUT ;
    USE SIGNAL ;
    SHAPE ABUTMENT ;
    PORT
      LAYER met2 ;
      RECT 333.890 0.000 334.030 0.420 ;
    END
  END rw0_rd_out[15]
  PIN rw0_rd_out[16]
    DIRECTION OUTPUT ;
    USE SIGNAL ;
    SHAPE ABUTMENT ;
    PORT
      LAYER met2 ;
      RECT 338.030 0.000 338.170 0.420 ;
    END
  END rw0_rd_out[16]
  PIN rw0_rd_out[17]
    DIRECTION OUTPUT ;
    USE SIGNAL ;
    SHAPE ABUTMENT ;
    PORT
      LAYER met2 ;
      RECT 342.170 0.000 342.310 0.420 ;
    END
  END rw0_rd_out[17]
  PIN rw0_rd_out[18]
    DIRECTION OUTPUT ;
    USE SIGNAL ;
    SHAPE ABUTMENT ;
    PORT
      LAYER met2 ;
      RECT 346.310 0.000 346.450 0.420 ;
    END
  END rw0_rd_out[18]
  PIN rw0_rd_out[19]
    DIRECTION OUTPUT ;
    USE SIGNAL ;
    SHAPE ABUTMENT ;
    PORT
      LAYER met2 ;
      RECT 350.450 0.000 350.590 0.420 ;
    END
  END rw0_rd_out[19]
  PIN rw0_rd_out[20]
    DIRECTION OUTPUT ;
    USE SIGNAL ;
    SHAPE ABUTMENT ;
    PORT
      LAYER met2 ;
      RECT 354.590 0.000 354.730 0.420 ;
    END
  END rw0_rd_out[20]
  PIN rw0_rd_out[21]
    DIRECTION OUTPUT ;
    USE SIGNAL ;
    SHAPE ABUTMENT ;
    PORT
      LAYER met2 ;
      RECT 358.730 0.000 358.870 0.420 ;
    END
  END rw0_rd_out[21]
  PIN rw0_rd_out[22]
    DIRECTION OUTPUT ;
    USE SIGNAL ;
    SHAPE ABUTMENT ;
    PORT
      LAYER met2 ;
      RECT 362.870 0.000 363.010 0.420 ;
    END
  END rw0_rd_out[22]
  PIN rw0_rd_out[23]
    DIRECTION OUTPUT ;
    USE SIGNAL ;
    SHAPE ABUTMENT ;
    PORT
      LAYER met2 ;
      RECT 367.010 0.000 367.150 0.420 ;
    END
  END rw0_rd_out[23]
  PIN rw0_rd_out[24]
    DIRECTION OUTPUT ;
    USE SIGNAL ;
    SHAPE ABUTMENT ;
    PORT
      LAYER met2 ;
      RECT 371.150 0.000 371.290 0.420 ;
    END
  END rw0_rd_out[24]
  PIN rw0_rd_out[25]
    DIRECTION OUTPUT ;
    USE SIGNAL ;
    SHAPE ABUTMENT ;
    PORT
      LAYER met2 ;
      RECT 375.290 0.000 375.430 0.420 ;
    END
  END rw0_rd_out[25]
  PIN rw0_rd_out[26]
    DIRECTION OUTPUT ;
    USE SIGNAL ;
    SHAPE ABUTMENT ;
    PORT
      LAYER met2 ;
      RECT 379.430 0.000 379.570 0.420 ;
    END
  END rw0_rd_out[26]
  PIN rw0_rd_out[27]
    DIRECTION OUTPUT ;
    USE SIGNAL ;
    SHAPE ABUTMENT ;
    PORT
      LAYER met2 ;
      RECT 383.570 0.000 383.710 0.420 ;
    END
  END rw0_rd_out[27]
  PIN rw0_rd_out[28]
    DIRECTION OUTPUT ;
    USE SIGNAL ;
    SHAPE ABUTMENT ;
    PORT
      LAYER met2 ;
      RECT 387.710 0.000 387.850 0.420 ;
    END
  END rw0_rd_out[28]
  PIN rw0_rd_out[29]
    DIRECTION OUTPUT ;
    USE SIGNAL ;
    SHAPE ABUTMENT ;
    PORT
      LAYER met2 ;
      RECT 391.850 0.000 391.990 0.420 ;
    END
  END rw0_rd_out[29]
  PIN rw0_rd_out[30]
    DIRECTION OUTPUT ;
    USE SIGNAL ;
    SHAPE ABUTMENT ;
    PORT
      LAYER met2 ;
      RECT 395.990 0.000 396.130 0.420 ;
    END
  END rw0_rd_out[30]
  PIN rw0_rd_out[31]
    DIRECTION OUTPUT ;
    USE SIGNAL ;
    SHAPE ABUTMENT ;
    PORT
      LAYER met2 ;
      RECT 400.130 0.000 400.270 0.420 ;
    END
  END rw0_rd_out[31]
  PIN rw0_rd_out[32]
    DIRECTION OUTPUT ;
    USE SIGNAL ;
    SHAPE ABUTMENT ;
    PORT
      LAYER met2 ;
      RECT 404.270 0.000 404.410 0.420 ;
    END
  END rw0_rd_out[32]
  PIN rw0_rd_out[33]
    DIRECTION OUTPUT ;
    USE SIGNAL ;
    SHAPE ABUTMENT ;
    PORT
      LAYER met2 ;
      RECT 408.410 0.000 408.550 0.420 ;
    END
  END rw0_rd_out[33]
  PIN rw0_rd_out[34]
    DIRECTION OUTPUT ;
    USE SIGNAL ;
    SHAPE ABUTMENT ;
    PORT
      LAYER met2 ;
      RECT 412.550 0.000 412.690 0.420 ;
    END
  END rw0_rd_out[34]
  PIN rw0_rd_out[35]
    DIRECTION OUTPUT ;
    USE SIGNAL ;
    SHAPE ABUTMENT ;
    PORT
      LAYER met2 ;
      RECT 416.690 0.000 416.830 0.420 ;
    END
  END rw0_rd_out[35]
  PIN rw0_rd_out[36]
    DIRECTION OUTPUT ;
    USE SIGNAL ;
    SHAPE ABUTMENT ;
    PORT
      LAYER met2 ;
      RECT 420.830 0.000 420.970 0.420 ;
    END
  END rw0_rd_out[36]
  PIN rw0_rd_out[37]
    DIRECTION OUTPUT ;
    USE SIGNAL ;
    SHAPE ABUTMENT ;
    PORT
      LAYER met2 ;
      RECT 424.970 0.000 425.110 0.420 ;
    END
  END rw0_rd_out[37]
  PIN rw0_rd_out[38]
    DIRECTION OUTPUT ;
    USE SIGNAL ;
    SHAPE ABUTMENT ;
    PORT
      LAYER met2 ;
      RECT 429.110 0.000 429.250 0.420 ;
    END
  END rw0_rd_out[38]
  PIN rw0_rd_out[39]
    DIRECTION OUTPUT ;
    USE SIGNAL ;
    SHAPE ABUTMENT ;
    PORT
      LAYER met2 ;
      RECT 433.250 0.000 433.390 0.420 ;
    END
  END rw0_rd_out[39]
  PIN rw0_rd_out[40]
    DIRECTION OUTPUT ;
    USE SIGNAL ;
    SHAPE ABUTMENT ;
    PORT
      LAYER met2 ;
      RECT 437.390 0.000 437.530 0.420 ;
    END
  END rw0_rd_out[40]
  PIN rw0_rd_out[41]
    DIRECTION OUTPUT ;
    USE SIGNAL ;
    SHAPE ABUTMENT ;
    PORT
      LAYER met2 ;
      RECT 441.530 0.000 441.670 0.420 ;
    END
  END rw0_rd_out[41]
  PIN rw0_rd_out[42]
    DIRECTION OUTPUT ;
    USE SIGNAL ;
    SHAPE ABUTMENT ;
    PORT
      LAYER met2 ;
      RECT 445.670 0.000 445.810 0.420 ;
    END
  END rw0_rd_out[42]
  PIN rw0_rd_out[43]
    DIRECTION OUTPUT ;
    USE SIGNAL ;
    SHAPE ABUTMENT ;
    PORT
      LAYER met2 ;
      RECT 449.810 0.000 449.950 0.420 ;
    END
  END rw0_rd_out[43]
  PIN rw0_rd_out[44]
    DIRECTION OUTPUT ;
    USE SIGNAL ;
    SHAPE ABUTMENT ;
    PORT
      LAYER met2 ;
      RECT 453.950 0.000 454.090 0.420 ;
    END
  END rw0_rd_out[44]
  PIN rw0_rd_out[45]
    DIRECTION OUTPUT ;
    USE SIGNAL ;
    SHAPE ABUTMENT ;
    PORT
      LAYER met2 ;
      RECT 458.090 0.000 458.230 0.420 ;
    END
  END rw0_rd_out[45]
  PIN rw0_rd_out[46]
    DIRECTION OUTPUT ;
    USE SIGNAL ;
    SHAPE ABUTMENT ;
    PORT
      LAYER met2 ;
      RECT 462.230 0.000 462.370 0.420 ;
    END
  END rw0_rd_out[46]
  PIN rw0_rd_out[47]
    DIRECTION OUTPUT ;
    USE SIGNAL ;
    SHAPE ABUTMENT ;
    PORT
      LAYER met2 ;
      RECT 466.370 0.000 466.510 0.420 ;
    END
  END rw0_rd_out[47]
  PIN rw0_rd_out[48]
    DIRECTION OUTPUT ;
    USE SIGNAL ;
    SHAPE ABUTMENT ;
    PORT
      LAYER met2 ;
      RECT 470.510 0.000 470.650 0.420 ;
    END
  END rw0_rd_out[48]
  PIN rw0_rd_out[49]
    DIRECTION OUTPUT ;
    USE SIGNAL ;
    SHAPE ABUTMENT ;
    PORT
      LAYER met2 ;
      RECT 474.650 0.000 474.790 0.420 ;
    END
  END rw0_rd_out[49]
  PIN rw0_rd_out[50]
    DIRECTION OUTPUT ;
    USE SIGNAL ;
    SHAPE ABUTMENT ;
    PORT
      LAYER met2 ;
      RECT 478.790 0.000 478.930 0.420 ;
    END
  END rw0_rd_out[50]
  PIN rw0_rd_out[51]
    DIRECTION OUTPUT ;
    USE SIGNAL ;
    SHAPE ABUTMENT ;
    PORT
      LAYER met2 ;
      RECT 482.930 0.000 483.070 0.420 ;
    END
  END rw0_rd_out[51]
  PIN rw0_rd_out[52]
    DIRECTION OUTPUT ;
    USE SIGNAL ;
    SHAPE ABUTMENT ;
    PORT
      LAYER met2 ;
      RECT 487.070 0.000 487.210 0.420 ;
    END
  END rw0_rd_out[52]
  PIN rw0_rd_out[53]
    DIRECTION OUTPUT ;
    USE SIGNAL ;
    SHAPE ABUTMENT ;
    PORT
      LAYER met2 ;
      RECT 491.210 0.000 491.350 0.420 ;
    END
  END rw0_rd_out[53]
  PIN rw0_rd_out[54]
    DIRECTION OUTPUT ;
    USE SIGNAL ;
    SHAPE ABUTMENT ;
    PORT
      LAYER met2 ;
      RECT 495.350 0.000 495.490 0.420 ;
    END
  END rw0_rd_out[54]
  PIN rw0_rd_out[55]
    DIRECTION OUTPUT ;
    USE SIGNAL ;
    SHAPE ABUTMENT ;
    PORT
      LAYER met2 ;
      RECT 499.490 0.000 499.630 0.420 ;
    END
  END rw0_rd_out[55]
  PIN rw0_rd_out[56]
    DIRECTION OUTPUT ;
    USE SIGNAL ;
    SHAPE ABUTMENT ;
    PORT
      LAYER met2 ;
      RECT 503.630 0.000 503.770 0.420 ;
    END
  END rw0_rd_out[56]
  PIN rw0_rd_out[57]
    DIRECTION OUTPUT ;
    USE SIGNAL ;
    SHAPE ABUTMENT ;
    PORT
      LAYER met2 ;
      RECT 507.770 0.000 507.910 0.420 ;
    END
  END rw0_rd_out[57]
  PIN rw0_rd_out[58]
    DIRECTION OUTPUT ;
    USE SIGNAL ;
    SHAPE ABUTMENT ;
    PORT
      LAYER met2 ;
      RECT 511.910 0.000 512.050 0.420 ;
    END
  END rw0_rd_out[58]
  PIN rw0_rd_out[59]
    DIRECTION OUTPUT ;
    USE SIGNAL ;
    SHAPE ABUTMENT ;
    PORT
      LAYER met2 ;
      RECT 516.050 0.000 516.190 0.420 ;
    END
  END rw0_rd_out[59]
  PIN rw0_rd_out[60]
    DIRECTION OUTPUT ;
    USE SIGNAL ;
    SHAPE ABUTMENT ;
    PORT
      LAYER met2 ;
      RECT 520.190 0.000 520.330 0.420 ;
    END
  END rw0_rd_out[60]
  PIN rw0_rd_out[61]
    DIRECTION OUTPUT ;
    USE SIGNAL ;
    SHAPE ABUTMENT ;
    PORT
      LAYER met2 ;
      RECT 524.330 0.000 524.470 0.420 ;
    END
  END rw0_rd_out[61]
  PIN rw0_rd_out[62]
    DIRECTION OUTPUT ;
    USE SIGNAL ;
    SHAPE ABUTMENT ;
    PORT
      LAYER met2 ;
      RECT 528.470 0.000 528.610 0.420 ;
    END
  END rw0_rd_out[62]
  PIN rw0_rd_out[63]
    DIRECTION OUTPUT ;
    USE SIGNAL ;
    SHAPE ABUTMENT ;
    PORT
      LAYER met2 ;
      RECT 532.610 0.000 532.750 0.420 ;
    END
  END rw0_rd_out[63]
  PIN rw0_rd_out[64]
    DIRECTION OUTPUT ;
    USE SIGNAL ;
    SHAPE ABUTMENT ;
    PORT
      LAYER met2 ;
      RECT 536.750 0.000 536.890 0.420 ;
    END
  END rw0_rd_out[64]
  PIN rw0_rd_out[65]
    DIRECTION OUTPUT ;
    USE SIGNAL ;
    SHAPE ABUTMENT ;
    PORT
      LAYER met2 ;
      RECT 2.690 856.380 2.830 856.800 ;
    END
  END rw0_rd_out[65]
  PIN rw0_rd_out[66]
    DIRECTION OUTPUT ;
    USE SIGNAL ;
    SHAPE ABUTMENT ;
    PORT
      LAYER met2 ;
      RECT 8.670 856.380 8.810 856.800 ;
    END
  END rw0_rd_out[66]
  PIN rw0_rd_out[67]
    DIRECTION OUTPUT ;
    USE SIGNAL ;
    SHAPE ABUTMENT ;
    PORT
      LAYER met2 ;
      RECT 14.650 856.380 14.790 856.800 ;
    END
  END rw0_rd_out[67]
  PIN rw0_rd_out[68]
    DIRECTION OUTPUT ;
    USE SIGNAL ;
    SHAPE ABUTMENT ;
    PORT
      LAYER met2 ;
      RECT 20.630 856.380 20.770 856.800 ;
    END
  END rw0_rd_out[68]
  PIN rw0_rd_out[69]
    DIRECTION OUTPUT ;
    USE SIGNAL ;
    SHAPE ABUTMENT ;
    PORT
      LAYER met2 ;
      RECT 26.610 856.380 26.750 856.800 ;
    END
  END rw0_rd_out[69]
  PIN rw0_rd_out[70]
    DIRECTION OUTPUT ;
    USE SIGNAL ;
    SHAPE ABUTMENT ;
    PORT
      LAYER met2 ;
      RECT 32.590 856.380 32.730 856.800 ;
    END
  END rw0_rd_out[70]
  PIN rw0_rd_out[71]
    DIRECTION OUTPUT ;
    USE SIGNAL ;
    SHAPE ABUTMENT ;
    PORT
      LAYER met2 ;
      RECT 38.570 856.380 38.710 856.800 ;
    END
  END rw0_rd_out[71]
  PIN rw0_rd_out[72]
    DIRECTION OUTPUT ;
    USE SIGNAL ;
    SHAPE ABUTMENT ;
    PORT
      LAYER met2 ;
      RECT 44.550 856.380 44.690 856.800 ;
    END
  END rw0_rd_out[72]
  PIN rw0_rd_out[73]
    DIRECTION OUTPUT ;
    USE SIGNAL ;
    SHAPE ABUTMENT ;
    PORT
      LAYER met2 ;
      RECT 50.530 856.380 50.670 856.800 ;
    END
  END rw0_rd_out[73]
  PIN rw0_rd_out[74]
    DIRECTION OUTPUT ;
    USE SIGNAL ;
    SHAPE ABUTMENT ;
    PORT
      LAYER met2 ;
      RECT 56.510 856.380 56.650 856.800 ;
    END
  END rw0_rd_out[74]
  PIN rw0_rd_out[75]
    DIRECTION OUTPUT ;
    USE SIGNAL ;
    SHAPE ABUTMENT ;
    PORT
      LAYER met2 ;
      RECT 62.490 856.380 62.630 856.800 ;
    END
  END rw0_rd_out[75]
  PIN rw0_rd_out[76]
    DIRECTION OUTPUT ;
    USE SIGNAL ;
    SHAPE ABUTMENT ;
    PORT
      LAYER met2 ;
      RECT 68.470 856.380 68.610 856.800 ;
    END
  END rw0_rd_out[76]
  PIN rw0_rd_out[77]
    DIRECTION OUTPUT ;
    USE SIGNAL ;
    SHAPE ABUTMENT ;
    PORT
      LAYER met2 ;
      RECT 74.450 856.380 74.590 856.800 ;
    END
  END rw0_rd_out[77]
  PIN rw0_rd_out[78]
    DIRECTION OUTPUT ;
    USE SIGNAL ;
    SHAPE ABUTMENT ;
    PORT
      LAYER met2 ;
      RECT 80.430 856.380 80.570 856.800 ;
    END
  END rw0_rd_out[78]
  PIN rw0_rd_out[79]
    DIRECTION OUTPUT ;
    USE SIGNAL ;
    SHAPE ABUTMENT ;
    PORT
      LAYER met2 ;
      RECT 86.410 856.380 86.550 856.800 ;
    END
  END rw0_rd_out[79]
  PIN rw0_rd_out[80]
    DIRECTION OUTPUT ;
    USE SIGNAL ;
    SHAPE ABUTMENT ;
    PORT
      LAYER met2 ;
      RECT 92.390 856.380 92.530 856.800 ;
    END
  END rw0_rd_out[80]
  PIN rw0_rd_out[81]
    DIRECTION OUTPUT ;
    USE SIGNAL ;
    SHAPE ABUTMENT ;
    PORT
      LAYER met2 ;
      RECT 98.370 856.380 98.510 856.800 ;
    END
  END rw0_rd_out[81]
  PIN rw0_rd_out[82]
    DIRECTION OUTPUT ;
    USE SIGNAL ;
    SHAPE ABUTMENT ;
    PORT
      LAYER met2 ;
      RECT 104.350 856.380 104.490 856.800 ;
    END
  END rw0_rd_out[82]
  PIN rw0_rd_out[83]
    DIRECTION OUTPUT ;
    USE SIGNAL ;
    SHAPE ABUTMENT ;
    PORT
      LAYER met2 ;
      RECT 110.330 856.380 110.470 856.800 ;
    END
  END rw0_rd_out[83]
  PIN rw0_rd_out[84]
    DIRECTION OUTPUT ;
    USE SIGNAL ;
    SHAPE ABUTMENT ;
    PORT
      LAYER met2 ;
      RECT 116.310 856.380 116.450 856.800 ;
    END
  END rw0_rd_out[84]
  PIN rw0_rd_out[85]
    DIRECTION OUTPUT ;
    USE SIGNAL ;
    SHAPE ABUTMENT ;
    PORT
      LAYER met2 ;
      RECT 122.290 856.380 122.430 856.800 ;
    END
  END rw0_rd_out[85]
  PIN rw0_rd_out[86]
    DIRECTION OUTPUT ;
    USE SIGNAL ;
    SHAPE ABUTMENT ;
    PORT
      LAYER met2 ;
      RECT 128.270 856.380 128.410 856.800 ;
    END
  END rw0_rd_out[86]
  PIN rw0_rd_out[87]
    DIRECTION OUTPUT ;
    USE SIGNAL ;
    SHAPE ABUTMENT ;
    PORT
      LAYER met2 ;
      RECT 134.250 856.380 134.390 856.800 ;
    END
  END rw0_rd_out[87]
  PIN rw0_rd_out[88]
    DIRECTION OUTPUT ;
    USE SIGNAL ;
    SHAPE ABUTMENT ;
    PORT
      LAYER met2 ;
      RECT 140.230 856.380 140.370 856.800 ;
    END
  END rw0_rd_out[88]
  PIN rw0_rd_out[89]
    DIRECTION OUTPUT ;
    USE SIGNAL ;
    SHAPE ABUTMENT ;
    PORT
      LAYER met2 ;
      RECT 146.210 856.380 146.350 856.800 ;
    END
  END rw0_rd_out[89]
  PIN rw0_rd_out[90]
    DIRECTION OUTPUT ;
    USE SIGNAL ;
    SHAPE ABUTMENT ;
    PORT
      LAYER met2 ;
      RECT 152.190 856.380 152.330 856.800 ;
    END
  END rw0_rd_out[90]
  PIN rw0_rd_out[91]
    DIRECTION OUTPUT ;
    USE SIGNAL ;
    SHAPE ABUTMENT ;
    PORT
      LAYER met2 ;
      RECT 158.170 856.380 158.310 856.800 ;
    END
  END rw0_rd_out[91]
  PIN rw0_rd_out[92]
    DIRECTION OUTPUT ;
    USE SIGNAL ;
    SHAPE ABUTMENT ;
    PORT
      LAYER met2 ;
      RECT 164.150 856.380 164.290 856.800 ;
    END
  END rw0_rd_out[92]
  PIN rw0_rd_out[93]
    DIRECTION OUTPUT ;
    USE SIGNAL ;
    SHAPE ABUTMENT ;
    PORT
      LAYER met2 ;
      RECT 170.130 856.380 170.270 856.800 ;
    END
  END rw0_rd_out[93]
  PIN rw0_rd_out[94]
    DIRECTION OUTPUT ;
    USE SIGNAL ;
    SHAPE ABUTMENT ;
    PORT
      LAYER met2 ;
      RECT 176.110 856.380 176.250 856.800 ;
    END
  END rw0_rd_out[94]
  PIN rw0_rd_out[95]
    DIRECTION OUTPUT ;
    USE SIGNAL ;
    SHAPE ABUTMENT ;
    PORT
      LAYER met2 ;
      RECT 182.090 856.380 182.230 856.800 ;
    END
  END rw0_rd_out[95]
  PIN rw0_rd_out[96]
    DIRECTION OUTPUT ;
    USE SIGNAL ;
    SHAPE ABUTMENT ;
    PORT
      LAYER met2 ;
      RECT 188.070 856.380 188.210 856.800 ;
    END
  END rw0_rd_out[96]
  PIN rw0_rd_out[97]
    DIRECTION OUTPUT ;
    USE SIGNAL ;
    SHAPE ABUTMENT ;
    PORT
      LAYER met2 ;
      RECT 194.050 856.380 194.190 856.800 ;
    END
  END rw0_rd_out[97]
  PIN rw0_rd_out[98]
    DIRECTION OUTPUT ;
    USE SIGNAL ;
    SHAPE ABUTMENT ;
    PORT
      LAYER met2 ;
      RECT 200.030 856.380 200.170 856.800 ;
    END
  END rw0_rd_out[98]
  PIN rw0_rd_out[99]
    DIRECTION OUTPUT ;
    USE SIGNAL ;
    SHAPE ABUTMENT ;
    PORT
      LAYER met2 ;
      RECT 206.010 856.380 206.150 856.800 ;
    END
  END rw0_rd_out[99]
  PIN rw0_rd_out[100]
    DIRECTION OUTPUT ;
    USE SIGNAL ;
    SHAPE ABUTMENT ;
    PORT
      LAYER met2 ;
      RECT 211.990 856.380 212.130 856.800 ;
    END
  END rw0_rd_out[100]
  PIN rw0_rd_out[101]
    DIRECTION OUTPUT ;
    USE SIGNAL ;
    SHAPE ABUTMENT ;
    PORT
      LAYER met2 ;
      RECT 217.970 856.380 218.110 856.800 ;
    END
  END rw0_rd_out[101]
  PIN rw0_rd_out[102]
    DIRECTION OUTPUT ;
    USE SIGNAL ;
    SHAPE ABUTMENT ;
    PORT
      LAYER met2 ;
      RECT 223.950 856.380 224.090 856.800 ;
    END
  END rw0_rd_out[102]
  PIN rw0_rd_out[103]
    DIRECTION OUTPUT ;
    USE SIGNAL ;
    SHAPE ABUTMENT ;
    PORT
      LAYER met2 ;
      RECT 229.930 856.380 230.070 856.800 ;
    END
  END rw0_rd_out[103]
  PIN rw0_rd_out[104]
    DIRECTION OUTPUT ;
    USE SIGNAL ;
    SHAPE ABUTMENT ;
    PORT
      LAYER met2 ;
      RECT 235.910 856.380 236.050 856.800 ;
    END
  END rw0_rd_out[104]
  PIN rw0_rd_out[105]
    DIRECTION OUTPUT ;
    USE SIGNAL ;
    SHAPE ABUTMENT ;
    PORT
      LAYER met2 ;
      RECT 241.890 856.380 242.030 856.800 ;
    END
  END rw0_rd_out[105]
  PIN rw0_rd_out[106]
    DIRECTION OUTPUT ;
    USE SIGNAL ;
    SHAPE ABUTMENT ;
    PORT
      LAYER met2 ;
      RECT 247.870 856.380 248.010 856.800 ;
    END
  END rw0_rd_out[106]
  PIN rw0_rd_out[107]
    DIRECTION OUTPUT ;
    USE SIGNAL ;
    SHAPE ABUTMENT ;
    PORT
      LAYER met2 ;
      RECT 253.850 856.380 253.990 856.800 ;
    END
  END rw0_rd_out[107]
  PIN rw0_rd_out[108]
    DIRECTION OUTPUT ;
    USE SIGNAL ;
    SHAPE ABUTMENT ;
    PORT
      LAYER met2 ;
      RECT 259.830 856.380 259.970 856.800 ;
    END
  END rw0_rd_out[108]
  PIN rw0_rd_out[109]
    DIRECTION OUTPUT ;
    USE SIGNAL ;
    SHAPE ABUTMENT ;
    PORT
      LAYER met2 ;
      RECT 265.810 856.380 265.950 856.800 ;
    END
  END rw0_rd_out[109]
  PIN rw0_rd_out[110]
    DIRECTION OUTPUT ;
    USE SIGNAL ;
    SHAPE ABUTMENT ;
    PORT
      LAYER met2 ;
      RECT 271.790 856.380 271.930 856.800 ;
    END
  END rw0_rd_out[110]
  PIN rw0_rd_out[111]
    DIRECTION OUTPUT ;
    USE SIGNAL ;
    SHAPE ABUTMENT ;
    PORT
      LAYER met2 ;
      RECT 277.770 856.380 277.910 856.800 ;
    END
  END rw0_rd_out[111]
  PIN rw0_rd_out[112]
    DIRECTION OUTPUT ;
    USE SIGNAL ;
    SHAPE ABUTMENT ;
    PORT
      LAYER met2 ;
      RECT 283.750 856.380 283.890 856.800 ;
    END
  END rw0_rd_out[112]
  PIN rw0_rd_out[113]
    DIRECTION OUTPUT ;
    USE SIGNAL ;
    SHAPE ABUTMENT ;
    PORT
      LAYER met2 ;
      RECT 289.730 856.380 289.870 856.800 ;
    END
  END rw0_rd_out[113]
  PIN rw0_rd_out[114]
    DIRECTION OUTPUT ;
    USE SIGNAL ;
    SHAPE ABUTMENT ;
    PORT
      LAYER met2 ;
      RECT 295.710 856.380 295.850 856.800 ;
    END
  END rw0_rd_out[114]
  PIN rw0_rd_out[115]
    DIRECTION OUTPUT ;
    USE SIGNAL ;
    SHAPE ABUTMENT ;
    PORT
      LAYER met2 ;
      RECT 301.690 856.380 301.830 856.800 ;
    END
  END rw0_rd_out[115]
  PIN rw0_rd_out[116]
    DIRECTION OUTPUT ;
    USE SIGNAL ;
    SHAPE ABUTMENT ;
    PORT
      LAYER met2 ;
      RECT 307.670 856.380 307.810 856.800 ;
    END
  END rw0_rd_out[116]
  PIN rw0_rd_out[117]
    DIRECTION OUTPUT ;
    USE SIGNAL ;
    SHAPE ABUTMENT ;
    PORT
      LAYER met2 ;
      RECT 313.650 856.380 313.790 856.800 ;
    END
  END rw0_rd_out[117]
  PIN rw0_rd_out[118]
    DIRECTION OUTPUT ;
    USE SIGNAL ;
    SHAPE ABUTMENT ;
    PORT
      LAYER met2 ;
      RECT 319.630 856.380 319.770 856.800 ;
    END
  END rw0_rd_out[118]
  PIN rw0_rd_out[119]
    DIRECTION OUTPUT ;
    USE SIGNAL ;
    SHAPE ABUTMENT ;
    PORT
      LAYER met2 ;
      RECT 325.610 856.380 325.750 856.800 ;
    END
  END rw0_rd_out[119]
  PIN rw0_rd_out[120]
    DIRECTION OUTPUT ;
    USE SIGNAL ;
    SHAPE ABUTMENT ;
    PORT
      LAYER met2 ;
      RECT 331.590 856.380 331.730 856.800 ;
    END
  END rw0_rd_out[120]
  PIN rw0_rd_out[121]
    DIRECTION OUTPUT ;
    USE SIGNAL ;
    SHAPE ABUTMENT ;
    PORT
      LAYER met2 ;
      RECT 337.570 856.380 337.710 856.800 ;
    END
  END rw0_rd_out[121]
  PIN rw0_rd_out[122]
    DIRECTION OUTPUT ;
    USE SIGNAL ;
    SHAPE ABUTMENT ;
    PORT
      LAYER met2 ;
      RECT 343.550 856.380 343.690 856.800 ;
    END
  END rw0_rd_out[122]
  PIN rw0_rd_out[123]
    DIRECTION OUTPUT ;
    USE SIGNAL ;
    SHAPE ABUTMENT ;
    PORT
      LAYER met2 ;
      RECT 349.530 856.380 349.670 856.800 ;
    END
  END rw0_rd_out[123]
  PIN rw0_rd_out[124]
    DIRECTION OUTPUT ;
    USE SIGNAL ;
    SHAPE ABUTMENT ;
    PORT
      LAYER met2 ;
      RECT 355.510 856.380 355.650 856.800 ;
    END
  END rw0_rd_out[124]
  PIN rw0_rd_out[125]
    DIRECTION OUTPUT ;
    USE SIGNAL ;
    SHAPE ABUTMENT ;
    PORT
      LAYER met2 ;
      RECT 361.490 856.380 361.630 856.800 ;
    END
  END rw0_rd_out[125]
  PIN rw0_rd_out[126]
    DIRECTION OUTPUT ;
    USE SIGNAL ;
    SHAPE ABUTMENT ;
    PORT
      LAYER met2 ;
      RECT 367.470 856.380 367.610 856.800 ;
    END
  END rw0_rd_out[126]
  PIN rw0_rd_out[127]
    DIRECTION OUTPUT ;
    USE SIGNAL ;
    SHAPE ABUTMENT ;
    PORT
      LAYER met2 ;
      RECT 373.450 856.380 373.590 856.800 ;
    END
  END rw0_rd_out[127]
  PIN rw0_rd_out[128]
    DIRECTION OUTPUT ;
    USE SIGNAL ;
    SHAPE ABUTMENT ;
    PORT
      LAYER met2 ;
      RECT 379.430 856.380 379.570 856.800 ;
    END
  END rw0_rd_out[128]
  PIN rw0_rd_out[129]
    DIRECTION OUTPUT ;
    USE SIGNAL ;
    SHAPE ABUTMENT ;
    PORT
      LAYER met2 ;
      RECT 385.410 856.380 385.550 856.800 ;
    END
  END rw0_rd_out[129]
  PIN r0_rd_out[0]
    DIRECTION OUTPUT ;
    USE SIGNAL ;
    SHAPE ABUTMENT ;
    PORT
      LAYER met2 ;
      RECT 540.890 0.000 541.030 0.420 ;
    END
  END r0_rd_out[0]
  PIN r0_rd_out[1]
    DIRECTION OUTPUT ;
    USE SIGNAL ;
    SHAPE ABUTMENT ;
    PORT
      LAYER met2 ;
      RECT 545.030 0.000 545.170 0.420 ;
    END
  END r0_rd_out[1]
  PIN r0_rd_out[2]
    DIRECTION OUTPUT ;
    USE SIGNAL ;
    SHAPE ABUTMENT ;
    PORT
      LAYER met2 ;
      RECT 549.170 0.000 549.310 0.420 ;
    END
  END r0_rd_out[2]
  PIN r0_rd_out[3]
    DIRECTION OUTPUT ;
    USE SIGNAL ;
    SHAPE ABUTMENT ;
    PORT
      LAYER met2 ;
      RECT 553.310 0.000 553.450 0.420 ;
    END
  END r0_rd_out[3]
  PIN r0_rd_out[4]
    DIRECTION OUTPUT ;
    USE SIGNAL ;
    SHAPE ABUTMENT ;
    PORT
      LAYER met2 ;
      RECT 557.450 0.000 557.590 0.420 ;
    END
  END r0_rd_out[4]
  PIN r0_rd_out[5]
    DIRECTION OUTPUT ;
    USE SIGNAL ;
    SHAPE ABUTMENT ;
    PORT
      LAYER met2 ;
      RECT 561.590 0.000 561.730 0.420 ;
    END
  END r0_rd_out[5]
  PIN r0_rd_out[6]
    DIRECTION OUTPUT ;
    USE SIGNAL ;
    SHAPE ABUTMENT ;
    PORT
      LAYER met2 ;
      RECT 565.730 0.000 565.870 0.420 ;
    END
  END r0_rd_out[6]
  PIN r0_rd_out[7]
    DIRECTION OUTPUT ;
    USE SIGNAL ;
    SHAPE ABUTMENT ;
    PORT
      LAYER met2 ;
      RECT 569.870 0.000 570.010 0.420 ;
    END
  END r0_rd_out[7]
  PIN r0_rd_out[8]
    DIRECTION OUTPUT ;
    USE SIGNAL ;
    SHAPE ABUTMENT ;
    PORT
      LAYER met2 ;
      RECT 574.010 0.000 574.150 0.420 ;
    END
  END r0_rd_out[8]
  PIN r0_rd_out[9]
    DIRECTION OUTPUT ;
    USE SIGNAL ;
    SHAPE ABUTMENT ;
    PORT
      LAYER met2 ;
      RECT 578.150 0.000 578.290 0.420 ;
    END
  END r0_rd_out[9]
  PIN r0_rd_out[10]
    DIRECTION OUTPUT ;
    USE SIGNAL ;
    SHAPE ABUTMENT ;
    PORT
      LAYER met2 ;
      RECT 582.290 0.000 582.430 0.420 ;
    END
  END r0_rd_out[10]
  PIN r0_rd_out[11]
    DIRECTION OUTPUT ;
    USE SIGNAL ;
    SHAPE ABUTMENT ;
    PORT
      LAYER met2 ;
      RECT 586.430 0.000 586.570 0.420 ;
    END
  END r0_rd_out[11]
  PIN r0_rd_out[12]
    DIRECTION OUTPUT ;
    USE SIGNAL ;
    SHAPE ABUTMENT ;
    PORT
      LAYER met2 ;
      RECT 590.570 0.000 590.710 0.420 ;
    END
  END r0_rd_out[12]
  PIN r0_rd_out[13]
    DIRECTION OUTPUT ;
    USE SIGNAL ;
    SHAPE ABUTMENT ;
    PORT
      LAYER met2 ;
      RECT 594.710 0.000 594.850 0.420 ;
    END
  END r0_rd_out[13]
  PIN r0_rd_out[14]
    DIRECTION OUTPUT ;
    USE SIGNAL ;
    SHAPE ABUTMENT ;
    PORT
      LAYER met2 ;
      RECT 598.850 0.000 598.990 0.420 ;
    END
  END r0_rd_out[14]
  PIN r0_rd_out[15]
    DIRECTION OUTPUT ;
    USE SIGNAL ;
    SHAPE ABUTMENT ;
    PORT
      LAYER met2 ;
      RECT 602.990 0.000 603.130 0.420 ;
    END
  END r0_rd_out[15]
  PIN r0_rd_out[16]
    DIRECTION OUTPUT ;
    USE SIGNAL ;
    SHAPE ABUTMENT ;
    PORT
      LAYER met2 ;
      RECT 607.130 0.000 607.270 0.420 ;
    END
  END r0_rd_out[16]
  PIN r0_rd_out[17]
    DIRECTION OUTPUT ;
    USE SIGNAL ;
    SHAPE ABUTMENT ;
    PORT
      LAYER met2 ;
      RECT 611.270 0.000 611.410 0.420 ;
    END
  END r0_rd_out[17]
  PIN r0_rd_out[18]
    DIRECTION OUTPUT ;
    USE SIGNAL ;
    SHAPE ABUTMENT ;
    PORT
      LAYER met2 ;
      RECT 615.410 0.000 615.550 0.420 ;
    END
  END r0_rd_out[18]
  PIN r0_rd_out[19]
    DIRECTION OUTPUT ;
    USE SIGNAL ;
    SHAPE ABUTMENT ;
    PORT
      LAYER met2 ;
      RECT 619.550 0.000 619.690 0.420 ;
    END
  END r0_rd_out[19]
  PIN r0_rd_out[20]
    DIRECTION OUTPUT ;
    USE SIGNAL ;
    SHAPE ABUTMENT ;
    PORT
      LAYER met2 ;
      RECT 623.690 0.000 623.830 0.420 ;
    END
  END r0_rd_out[20]
  PIN r0_rd_out[21]
    DIRECTION OUTPUT ;
    USE SIGNAL ;
    SHAPE ABUTMENT ;
    PORT
      LAYER met2 ;
      RECT 627.830 0.000 627.970 0.420 ;
    END
  END r0_rd_out[21]
  PIN r0_rd_out[22]
    DIRECTION OUTPUT ;
    USE SIGNAL ;
    SHAPE ABUTMENT ;
    PORT
      LAYER met2 ;
      RECT 631.970 0.000 632.110 0.420 ;
    END
  END r0_rd_out[22]
  PIN r0_rd_out[23]
    DIRECTION OUTPUT ;
    USE SIGNAL ;
    SHAPE ABUTMENT ;
    PORT
      LAYER met2 ;
      RECT 636.110 0.000 636.250 0.420 ;
    END
  END r0_rd_out[23]
  PIN r0_rd_out[24]
    DIRECTION OUTPUT ;
    USE SIGNAL ;
    SHAPE ABUTMENT ;
    PORT
      LAYER met2 ;
      RECT 640.250 0.000 640.390 0.420 ;
    END
  END r0_rd_out[24]
  PIN r0_rd_out[25]
    DIRECTION OUTPUT ;
    USE SIGNAL ;
    SHAPE ABUTMENT ;
    PORT
      LAYER met2 ;
      RECT 644.390 0.000 644.530 0.420 ;
    END
  END r0_rd_out[25]
  PIN r0_rd_out[26]
    DIRECTION OUTPUT ;
    USE SIGNAL ;
    SHAPE ABUTMENT ;
    PORT
      LAYER met2 ;
      RECT 648.530 0.000 648.670 0.420 ;
    END
  END r0_rd_out[26]
  PIN r0_rd_out[27]
    DIRECTION OUTPUT ;
    USE SIGNAL ;
    SHAPE ABUTMENT ;
    PORT
      LAYER met2 ;
      RECT 652.670 0.000 652.810 0.420 ;
    END
  END r0_rd_out[27]
  PIN r0_rd_out[28]
    DIRECTION OUTPUT ;
    USE SIGNAL ;
    SHAPE ABUTMENT ;
    PORT
      LAYER met2 ;
      RECT 656.810 0.000 656.950 0.420 ;
    END
  END r0_rd_out[28]
  PIN r0_rd_out[29]
    DIRECTION OUTPUT ;
    USE SIGNAL ;
    SHAPE ABUTMENT ;
    PORT
      LAYER met2 ;
      RECT 660.950 0.000 661.090 0.420 ;
    END
  END r0_rd_out[29]
  PIN r0_rd_out[30]
    DIRECTION OUTPUT ;
    USE SIGNAL ;
    SHAPE ABUTMENT ;
    PORT
      LAYER met2 ;
      RECT 665.090 0.000 665.230 0.420 ;
    END
  END r0_rd_out[30]
  PIN r0_rd_out[31]
    DIRECTION OUTPUT ;
    USE SIGNAL ;
    SHAPE ABUTMENT ;
    PORT
      LAYER met2 ;
      RECT 669.230 0.000 669.370 0.420 ;
    END
  END r0_rd_out[31]
  PIN r0_rd_out[32]
    DIRECTION OUTPUT ;
    USE SIGNAL ;
    SHAPE ABUTMENT ;
    PORT
      LAYER met2 ;
      RECT 673.370 0.000 673.510 0.420 ;
    END
  END r0_rd_out[32]
  PIN r0_rd_out[33]
    DIRECTION OUTPUT ;
    USE SIGNAL ;
    SHAPE ABUTMENT ;
    PORT
      LAYER met2 ;
      RECT 677.510 0.000 677.650 0.420 ;
    END
  END r0_rd_out[33]
  PIN r0_rd_out[34]
    DIRECTION OUTPUT ;
    USE SIGNAL ;
    SHAPE ABUTMENT ;
    PORT
      LAYER met2 ;
      RECT 681.650 0.000 681.790 0.420 ;
    END
  END r0_rd_out[34]
  PIN r0_rd_out[35]
    DIRECTION OUTPUT ;
    USE SIGNAL ;
    SHAPE ABUTMENT ;
    PORT
      LAYER met2 ;
      RECT 685.790 0.000 685.930 0.420 ;
    END
  END r0_rd_out[35]
  PIN r0_rd_out[36]
    DIRECTION OUTPUT ;
    USE SIGNAL ;
    SHAPE ABUTMENT ;
    PORT
      LAYER met2 ;
      RECT 689.930 0.000 690.070 0.420 ;
    END
  END r0_rd_out[36]
  PIN r0_rd_out[37]
    DIRECTION OUTPUT ;
    USE SIGNAL ;
    SHAPE ABUTMENT ;
    PORT
      LAYER met2 ;
      RECT 694.070 0.000 694.210 0.420 ;
    END
  END r0_rd_out[37]
  PIN r0_rd_out[38]
    DIRECTION OUTPUT ;
    USE SIGNAL ;
    SHAPE ABUTMENT ;
    PORT
      LAYER met2 ;
      RECT 698.210 0.000 698.350 0.420 ;
    END
  END r0_rd_out[38]
  PIN r0_rd_out[39]
    DIRECTION OUTPUT ;
    USE SIGNAL ;
    SHAPE ABUTMENT ;
    PORT
      LAYER met2 ;
      RECT 702.350 0.000 702.490 0.420 ;
    END
  END r0_rd_out[39]
  PIN r0_rd_out[40]
    DIRECTION OUTPUT ;
    USE SIGNAL ;
    SHAPE ABUTMENT ;
    PORT
      LAYER met2 ;
      RECT 706.490 0.000 706.630 0.420 ;
    END
  END r0_rd_out[40]
  PIN r0_rd_out[41]
    DIRECTION OUTPUT ;
    USE SIGNAL ;
    SHAPE ABUTMENT ;
    PORT
      LAYER met2 ;
      RECT 710.630 0.000 710.770 0.420 ;
    END
  END r0_rd_out[41]
  PIN r0_rd_out[42]
    DIRECTION OUTPUT ;
    USE SIGNAL ;
    SHAPE ABUTMENT ;
    PORT
      LAYER met2 ;
      RECT 714.770 0.000 714.910 0.420 ;
    END
  END r0_rd_out[42]
  PIN r0_rd_out[43]
    DIRECTION OUTPUT ;
    USE SIGNAL ;
    SHAPE ABUTMENT ;
    PORT
      LAYER met2 ;
      RECT 718.910 0.000 719.050 0.420 ;
    END
  END r0_rd_out[43]
  PIN r0_rd_out[44]
    DIRECTION OUTPUT ;
    USE SIGNAL ;
    SHAPE ABUTMENT ;
    PORT
      LAYER met2 ;
      RECT 723.050 0.000 723.190 0.420 ;
    END
  END r0_rd_out[44]
  PIN r0_rd_out[45]
    DIRECTION OUTPUT ;
    USE SIGNAL ;
    SHAPE ABUTMENT ;
    PORT
      LAYER met2 ;
      RECT 727.190 0.000 727.330 0.420 ;
    END
  END r0_rd_out[45]
  PIN r0_rd_out[46]
    DIRECTION OUTPUT ;
    USE SIGNAL ;
    SHAPE ABUTMENT ;
    PORT
      LAYER met2 ;
      RECT 731.330 0.000 731.470 0.420 ;
    END
  END r0_rd_out[46]
  PIN r0_rd_out[47]
    DIRECTION OUTPUT ;
    USE SIGNAL ;
    SHAPE ABUTMENT ;
    PORT
      LAYER met2 ;
      RECT 735.470 0.000 735.610 0.420 ;
    END
  END r0_rd_out[47]
  PIN r0_rd_out[48]
    DIRECTION OUTPUT ;
    USE SIGNAL ;
    SHAPE ABUTMENT ;
    PORT
      LAYER met2 ;
      RECT 739.610 0.000 739.750 0.420 ;
    END
  END r0_rd_out[48]
  PIN r0_rd_out[49]
    DIRECTION OUTPUT ;
    USE SIGNAL ;
    SHAPE ABUTMENT ;
    PORT
      LAYER met2 ;
      RECT 743.750 0.000 743.890 0.420 ;
    END
  END r0_rd_out[49]
  PIN r0_rd_out[50]
    DIRECTION OUTPUT ;
    USE SIGNAL ;
    SHAPE ABUTMENT ;
    PORT
      LAYER met2 ;
      RECT 747.890 0.000 748.030 0.420 ;
    END
  END r0_rd_out[50]
  PIN r0_rd_out[51]
    DIRECTION OUTPUT ;
    USE SIGNAL ;
    SHAPE ABUTMENT ;
    PORT
      LAYER met2 ;
      RECT 752.030 0.000 752.170 0.420 ;
    END
  END r0_rd_out[51]
  PIN r0_rd_out[52]
    DIRECTION OUTPUT ;
    USE SIGNAL ;
    SHAPE ABUTMENT ;
    PORT
      LAYER met2 ;
      RECT 756.170 0.000 756.310 0.420 ;
    END
  END r0_rd_out[52]
  PIN r0_rd_out[53]
    DIRECTION OUTPUT ;
    USE SIGNAL ;
    SHAPE ABUTMENT ;
    PORT
      LAYER met2 ;
      RECT 760.310 0.000 760.450 0.420 ;
    END
  END r0_rd_out[53]
  PIN r0_rd_out[54]
    DIRECTION OUTPUT ;
    USE SIGNAL ;
    SHAPE ABUTMENT ;
    PORT
      LAYER met2 ;
      RECT 764.450 0.000 764.590 0.420 ;
    END
  END r0_rd_out[54]
  PIN r0_rd_out[55]
    DIRECTION OUTPUT ;
    USE SIGNAL ;
    SHAPE ABUTMENT ;
    PORT
      LAYER met2 ;
      RECT 768.590 0.000 768.730 0.420 ;
    END
  END r0_rd_out[55]
  PIN r0_rd_out[56]
    DIRECTION OUTPUT ;
    USE SIGNAL ;
    SHAPE ABUTMENT ;
    PORT
      LAYER met2 ;
      RECT 772.730 0.000 772.870 0.420 ;
    END
  END r0_rd_out[56]
  PIN r0_rd_out[57]
    DIRECTION OUTPUT ;
    USE SIGNAL ;
    SHAPE ABUTMENT ;
    PORT
      LAYER met2 ;
      RECT 776.870 0.000 777.010 0.420 ;
    END
  END r0_rd_out[57]
  PIN r0_rd_out[58]
    DIRECTION OUTPUT ;
    USE SIGNAL ;
    SHAPE ABUTMENT ;
    PORT
      LAYER met2 ;
      RECT 781.010 0.000 781.150 0.420 ;
    END
  END r0_rd_out[58]
  PIN r0_rd_out[59]
    DIRECTION OUTPUT ;
    USE SIGNAL ;
    SHAPE ABUTMENT ;
    PORT
      LAYER met2 ;
      RECT 785.150 0.000 785.290 0.420 ;
    END
  END r0_rd_out[59]
  PIN r0_rd_out[60]
    DIRECTION OUTPUT ;
    USE SIGNAL ;
    SHAPE ABUTMENT ;
    PORT
      LAYER met2 ;
      RECT 789.290 0.000 789.430 0.420 ;
    END
  END r0_rd_out[60]
  PIN r0_rd_out[61]
    DIRECTION OUTPUT ;
    USE SIGNAL ;
    SHAPE ABUTMENT ;
    PORT
      LAYER met2 ;
      RECT 793.430 0.000 793.570 0.420 ;
    END
  END r0_rd_out[61]
  PIN r0_rd_out[62]
    DIRECTION OUTPUT ;
    USE SIGNAL ;
    SHAPE ABUTMENT ;
    PORT
      LAYER met2 ;
      RECT 797.570 0.000 797.710 0.420 ;
    END
  END r0_rd_out[62]
  PIN r0_rd_out[63]
    DIRECTION OUTPUT ;
    USE SIGNAL ;
    SHAPE ABUTMENT ;
    PORT
      LAYER met2 ;
      RECT 801.710 0.000 801.850 0.420 ;
    END
  END r0_rd_out[63]
  PIN r0_rd_out[64]
    DIRECTION OUTPUT ;
    USE SIGNAL ;
    SHAPE ABUTMENT ;
    PORT
      LAYER met2 ;
      RECT 805.850 0.000 805.990 0.420 ;
    END
  END r0_rd_out[64]
  PIN r0_rd_out[65]
    DIRECTION OUTPUT ;
    USE SIGNAL ;
    SHAPE ABUTMENT ;
    PORT
      LAYER met2 ;
      RECT 391.390 856.380 391.530 856.800 ;
    END
  END r0_rd_out[65]
  PIN r0_rd_out[66]
    DIRECTION OUTPUT ;
    USE SIGNAL ;
    SHAPE ABUTMENT ;
    PORT
      LAYER met2 ;
      RECT 397.370 856.380 397.510 856.800 ;
    END
  END r0_rd_out[66]
  PIN r0_rd_out[67]
    DIRECTION OUTPUT ;
    USE SIGNAL ;
    SHAPE ABUTMENT ;
    PORT
      LAYER met2 ;
      RECT 403.350 856.380 403.490 856.800 ;
    END
  END r0_rd_out[67]
  PIN r0_rd_out[68]
    DIRECTION OUTPUT ;
    USE SIGNAL ;
    SHAPE ABUTMENT ;
    PORT
      LAYER met2 ;
      RECT 409.330 856.380 409.470 856.800 ;
    END
  END r0_rd_out[68]
  PIN r0_rd_out[69]
    DIRECTION OUTPUT ;
    USE SIGNAL ;
    SHAPE ABUTMENT ;
    PORT
      LAYER met2 ;
      RECT 415.310 856.380 415.450 856.800 ;
    END
  END r0_rd_out[69]
  PIN r0_rd_out[70]
    DIRECTION OUTPUT ;
    USE SIGNAL ;
    SHAPE ABUTMENT ;
    PORT
      LAYER met2 ;
      RECT 421.290 856.380 421.430 856.800 ;
    END
  END r0_rd_out[70]
  PIN r0_rd_out[71]
    DIRECTION OUTPUT ;
    USE SIGNAL ;
    SHAPE ABUTMENT ;
    PORT
      LAYER met2 ;
      RECT 427.270 856.380 427.410 856.800 ;
    END
  END r0_rd_out[71]
  PIN r0_rd_out[72]
    DIRECTION OUTPUT ;
    USE SIGNAL ;
    SHAPE ABUTMENT ;
    PORT
      LAYER met2 ;
      RECT 433.250 856.380 433.390 856.800 ;
    END
  END r0_rd_out[72]
  PIN r0_rd_out[73]
    DIRECTION OUTPUT ;
    USE SIGNAL ;
    SHAPE ABUTMENT ;
    PORT
      LAYER met2 ;
      RECT 439.230 856.380 439.370 856.800 ;
    END
  END r0_rd_out[73]
  PIN r0_rd_out[74]
    DIRECTION OUTPUT ;
    USE SIGNAL ;
    SHAPE ABUTMENT ;
    PORT
      LAYER met2 ;
      RECT 445.210 856.380 445.350 856.800 ;
    END
  END r0_rd_out[74]
  PIN r0_rd_out[75]
    DIRECTION OUTPUT ;
    USE SIGNAL ;
    SHAPE ABUTMENT ;
    PORT
      LAYER met2 ;
      RECT 451.190 856.380 451.330 856.800 ;
    END
  END r0_rd_out[75]
  PIN r0_rd_out[76]
    DIRECTION OUTPUT ;
    USE SIGNAL ;
    SHAPE ABUTMENT ;
    PORT
      LAYER met2 ;
      RECT 457.170 856.380 457.310 856.800 ;
    END
  END r0_rd_out[76]
  PIN r0_rd_out[77]
    DIRECTION OUTPUT ;
    USE SIGNAL ;
    SHAPE ABUTMENT ;
    PORT
      LAYER met2 ;
      RECT 463.150 856.380 463.290 856.800 ;
    END
  END r0_rd_out[77]
  PIN r0_rd_out[78]
    DIRECTION OUTPUT ;
    USE SIGNAL ;
    SHAPE ABUTMENT ;
    PORT
      LAYER met2 ;
      RECT 469.130 856.380 469.270 856.800 ;
    END
  END r0_rd_out[78]
  PIN r0_rd_out[79]
    DIRECTION OUTPUT ;
    USE SIGNAL ;
    SHAPE ABUTMENT ;
    PORT
      LAYER met2 ;
      RECT 475.110 856.380 475.250 856.800 ;
    END
  END r0_rd_out[79]
  PIN r0_rd_out[80]
    DIRECTION OUTPUT ;
    USE SIGNAL ;
    SHAPE ABUTMENT ;
    PORT
      LAYER met2 ;
      RECT 481.090 856.380 481.230 856.800 ;
    END
  END r0_rd_out[80]
  PIN r0_rd_out[81]
    DIRECTION OUTPUT ;
    USE SIGNAL ;
    SHAPE ABUTMENT ;
    PORT
      LAYER met2 ;
      RECT 487.070 856.380 487.210 856.800 ;
    END
  END r0_rd_out[81]
  PIN r0_rd_out[82]
    DIRECTION OUTPUT ;
    USE SIGNAL ;
    SHAPE ABUTMENT ;
    PORT
      LAYER met2 ;
      RECT 493.050 856.380 493.190 856.800 ;
    END
  END r0_rd_out[82]
  PIN r0_rd_out[83]
    DIRECTION OUTPUT ;
    USE SIGNAL ;
    SHAPE ABUTMENT ;
    PORT
      LAYER met2 ;
      RECT 499.030 856.380 499.170 856.800 ;
    END
  END r0_rd_out[83]
  PIN r0_rd_out[84]
    DIRECTION OUTPUT ;
    USE SIGNAL ;
    SHAPE ABUTMENT ;
    PORT
      LAYER met2 ;
      RECT 505.010 856.380 505.150 856.800 ;
    END
  END r0_rd_out[84]
  PIN r0_rd_out[85]
    DIRECTION OUTPUT ;
    USE SIGNAL ;
    SHAPE ABUTMENT ;
    PORT
      LAYER met2 ;
      RECT 510.990 856.380 511.130 856.800 ;
    END
  END r0_rd_out[85]
  PIN r0_rd_out[86]
    DIRECTION OUTPUT ;
    USE SIGNAL ;
    SHAPE ABUTMENT ;
    PORT
      LAYER met2 ;
      RECT 516.970 856.380 517.110 856.800 ;
    END
  END r0_rd_out[86]
  PIN r0_rd_out[87]
    DIRECTION OUTPUT ;
    USE SIGNAL ;
    SHAPE ABUTMENT ;
    PORT
      LAYER met2 ;
      RECT 522.950 856.380 523.090 856.800 ;
    END
  END r0_rd_out[87]
  PIN r0_rd_out[88]
    DIRECTION OUTPUT ;
    USE SIGNAL ;
    SHAPE ABUTMENT ;
    PORT
      LAYER met2 ;
      RECT 528.930 856.380 529.070 856.800 ;
    END
  END r0_rd_out[88]
  PIN r0_rd_out[89]
    DIRECTION OUTPUT ;
    USE SIGNAL ;
    SHAPE ABUTMENT ;
    PORT
      LAYER met2 ;
      RECT 534.910 856.380 535.050 856.800 ;
    END
  END r0_rd_out[89]
  PIN r0_rd_out[90]
    DIRECTION OUTPUT ;
    USE SIGNAL ;
    SHAPE ABUTMENT ;
    PORT
      LAYER met2 ;
      RECT 540.890 856.380 541.030 856.800 ;
    END
  END r0_rd_out[90]
  PIN r0_rd_out[91]
    DIRECTION OUTPUT ;
    USE SIGNAL ;
    SHAPE ABUTMENT ;
    PORT
      LAYER met2 ;
      RECT 546.870 856.380 547.010 856.800 ;
    END
  END r0_rd_out[91]
  PIN r0_rd_out[92]
    DIRECTION OUTPUT ;
    USE SIGNAL ;
    SHAPE ABUTMENT ;
    PORT
      LAYER met2 ;
      RECT 552.850 856.380 552.990 856.800 ;
    END
  END r0_rd_out[92]
  PIN r0_rd_out[93]
    DIRECTION OUTPUT ;
    USE SIGNAL ;
    SHAPE ABUTMENT ;
    PORT
      LAYER met2 ;
      RECT 558.830 856.380 558.970 856.800 ;
    END
  END r0_rd_out[93]
  PIN r0_rd_out[94]
    DIRECTION OUTPUT ;
    USE SIGNAL ;
    SHAPE ABUTMENT ;
    PORT
      LAYER met2 ;
      RECT 564.810 856.380 564.950 856.800 ;
    END
  END r0_rd_out[94]
  PIN r0_rd_out[95]
    DIRECTION OUTPUT ;
    USE SIGNAL ;
    SHAPE ABUTMENT ;
    PORT
      LAYER met2 ;
      RECT 570.790 856.380 570.930 856.800 ;
    END
  END r0_rd_out[95]
  PIN r0_rd_out[96]
    DIRECTION OUTPUT ;
    USE SIGNAL ;
    SHAPE ABUTMENT ;
    PORT
      LAYER met2 ;
      RECT 576.770 856.380 576.910 856.800 ;
    END
  END r0_rd_out[96]
  PIN r0_rd_out[97]
    DIRECTION OUTPUT ;
    USE SIGNAL ;
    SHAPE ABUTMENT ;
    PORT
      LAYER met2 ;
      RECT 582.750 856.380 582.890 856.800 ;
    END
  END r0_rd_out[97]
  PIN r0_rd_out[98]
    DIRECTION OUTPUT ;
    USE SIGNAL ;
    SHAPE ABUTMENT ;
    PORT
      LAYER met2 ;
      RECT 588.730 856.380 588.870 856.800 ;
    END
  END r0_rd_out[98]
  PIN r0_rd_out[99]
    DIRECTION OUTPUT ;
    USE SIGNAL ;
    SHAPE ABUTMENT ;
    PORT
      LAYER met2 ;
      RECT 594.710 856.380 594.850 856.800 ;
    END
  END r0_rd_out[99]
  PIN r0_rd_out[100]
    DIRECTION OUTPUT ;
    USE SIGNAL ;
    SHAPE ABUTMENT ;
    PORT
      LAYER met2 ;
      RECT 600.690 856.380 600.830 856.800 ;
    END
  END r0_rd_out[100]
  PIN r0_rd_out[101]
    DIRECTION OUTPUT ;
    USE SIGNAL ;
    SHAPE ABUTMENT ;
    PORT
      LAYER met2 ;
      RECT 606.670 856.380 606.810 856.800 ;
    END
  END r0_rd_out[101]
  PIN r0_rd_out[102]
    DIRECTION OUTPUT ;
    USE SIGNAL ;
    SHAPE ABUTMENT ;
    PORT
      LAYER met2 ;
      RECT 612.650 856.380 612.790 856.800 ;
    END
  END r0_rd_out[102]
  PIN r0_rd_out[103]
    DIRECTION OUTPUT ;
    USE SIGNAL ;
    SHAPE ABUTMENT ;
    PORT
      LAYER met2 ;
      RECT 618.630 856.380 618.770 856.800 ;
    END
  END r0_rd_out[103]
  PIN r0_rd_out[104]
    DIRECTION OUTPUT ;
    USE SIGNAL ;
    SHAPE ABUTMENT ;
    PORT
      LAYER met2 ;
      RECT 624.610 856.380 624.750 856.800 ;
    END
  END r0_rd_out[104]
  PIN r0_rd_out[105]
    DIRECTION OUTPUT ;
    USE SIGNAL ;
    SHAPE ABUTMENT ;
    PORT
      LAYER met2 ;
      RECT 630.590 856.380 630.730 856.800 ;
    END
  END r0_rd_out[105]
  PIN r0_rd_out[106]
    DIRECTION OUTPUT ;
    USE SIGNAL ;
    SHAPE ABUTMENT ;
    PORT
      LAYER met2 ;
      RECT 636.570 856.380 636.710 856.800 ;
    END
  END r0_rd_out[106]
  PIN r0_rd_out[107]
    DIRECTION OUTPUT ;
    USE SIGNAL ;
    SHAPE ABUTMENT ;
    PORT
      LAYER met2 ;
      RECT 642.550 856.380 642.690 856.800 ;
    END
  END r0_rd_out[107]
  PIN r0_rd_out[108]
    DIRECTION OUTPUT ;
    USE SIGNAL ;
    SHAPE ABUTMENT ;
    PORT
      LAYER met2 ;
      RECT 648.530 856.380 648.670 856.800 ;
    END
  END r0_rd_out[108]
  PIN r0_rd_out[109]
    DIRECTION OUTPUT ;
    USE SIGNAL ;
    SHAPE ABUTMENT ;
    PORT
      LAYER met2 ;
      RECT 654.510 856.380 654.650 856.800 ;
    END
  END r0_rd_out[109]
  PIN r0_rd_out[110]
    DIRECTION OUTPUT ;
    USE SIGNAL ;
    SHAPE ABUTMENT ;
    PORT
      LAYER met2 ;
      RECT 660.490 856.380 660.630 856.800 ;
    END
  END r0_rd_out[110]
  PIN r0_rd_out[111]
    DIRECTION OUTPUT ;
    USE SIGNAL ;
    SHAPE ABUTMENT ;
    PORT
      LAYER met2 ;
      RECT 666.470 856.380 666.610 856.800 ;
    END
  END r0_rd_out[111]
  PIN r0_rd_out[112]
    DIRECTION OUTPUT ;
    USE SIGNAL ;
    SHAPE ABUTMENT ;
    PORT
      LAYER met2 ;
      RECT 672.450 856.380 672.590 856.800 ;
    END
  END r0_rd_out[112]
  PIN r0_rd_out[113]
    DIRECTION OUTPUT ;
    USE SIGNAL ;
    SHAPE ABUTMENT ;
    PORT
      LAYER met2 ;
      RECT 678.430 856.380 678.570 856.800 ;
    END
  END r0_rd_out[113]
  PIN r0_rd_out[114]
    DIRECTION OUTPUT ;
    USE SIGNAL ;
    SHAPE ABUTMENT ;
    PORT
      LAYER met2 ;
      RECT 684.410 856.380 684.550 856.800 ;
    END
  END r0_rd_out[114]
  PIN r0_rd_out[115]
    DIRECTION OUTPUT ;
    USE SIGNAL ;
    SHAPE ABUTMENT ;
    PORT
      LAYER met2 ;
      RECT 690.390 856.380 690.530 856.800 ;
    END
  END r0_rd_out[115]
  PIN r0_rd_out[116]
    DIRECTION OUTPUT ;
    USE SIGNAL ;
    SHAPE ABUTMENT ;
    PORT
      LAYER met2 ;
      RECT 696.370 856.380 696.510 856.800 ;
    END
  END r0_rd_out[116]
  PIN r0_rd_out[117]
    DIRECTION OUTPUT ;
    USE SIGNAL ;
    SHAPE ABUTMENT ;
    PORT
      LAYER met2 ;
      RECT 702.350 856.380 702.490 856.800 ;
    END
  END r0_rd_out[117]
  PIN r0_rd_out[118]
    DIRECTION OUTPUT ;
    USE SIGNAL ;
    SHAPE ABUTMENT ;
    PORT
      LAYER met2 ;
      RECT 708.330 856.380 708.470 856.800 ;
    END
  END r0_rd_out[118]
  PIN r0_rd_out[119]
    DIRECTION OUTPUT ;
    USE SIGNAL ;
    SHAPE ABUTMENT ;
    PORT
      LAYER met2 ;
      RECT 714.310 856.380 714.450 856.800 ;
    END
  END r0_rd_out[119]
  PIN r0_rd_out[120]
    DIRECTION OUTPUT ;
    USE SIGNAL ;
    SHAPE ABUTMENT ;
    PORT
      LAYER met2 ;
      RECT 720.290 856.380 720.430 856.800 ;
    END
  END r0_rd_out[120]
  PIN r0_rd_out[121]
    DIRECTION OUTPUT ;
    USE SIGNAL ;
    SHAPE ABUTMENT ;
    PORT
      LAYER met2 ;
      RECT 726.270 856.380 726.410 856.800 ;
    END
  END r0_rd_out[121]
  PIN r0_rd_out[122]
    DIRECTION OUTPUT ;
    USE SIGNAL ;
    SHAPE ABUTMENT ;
    PORT
      LAYER met2 ;
      RECT 732.250 856.380 732.390 856.800 ;
    END
  END r0_rd_out[122]
  PIN r0_rd_out[123]
    DIRECTION OUTPUT ;
    USE SIGNAL ;
    SHAPE ABUTMENT ;
    PORT
      LAYER met2 ;
      RECT 738.230 856.380 738.370 856.800 ;
    END
  END r0_rd_out[123]
  PIN r0_rd_out[124]
    DIRECTION OUTPUT ;
    USE SIGNAL ;
    SHAPE ABUTMENT ;
    PORT
      LAYER met2 ;
      RECT 744.210 856.380 744.350 856.800 ;
    END
  END r0_rd_out[124]
  PIN r0_rd_out[125]
    DIRECTION OUTPUT ;
    USE SIGNAL ;
    SHAPE ABUTMENT ;
    PORT
      LAYER met2 ;
      RECT 750.190 856.380 750.330 856.800 ;
    END
  END r0_rd_out[125]
  PIN r0_rd_out[126]
    DIRECTION OUTPUT ;
    USE SIGNAL ;
    SHAPE ABUTMENT ;
    PORT
      LAYER met2 ;
      RECT 756.170 856.380 756.310 856.800 ;
    END
  END r0_rd_out[126]
  PIN r0_rd_out[127]
    DIRECTION OUTPUT ;
    USE SIGNAL ;
    SHAPE ABUTMENT ;
    PORT
      LAYER met2 ;
      RECT 762.150 856.380 762.290 856.800 ;
    END
  END r0_rd_out[127]
  PIN r0_rd_out[128]
    DIRECTION OUTPUT ;
    USE SIGNAL ;
    SHAPE ABUTMENT ;
    PORT
      LAYER met2 ;
      RECT 768.130 856.380 768.270 856.800 ;
    END
  END r0_rd_out[128]
  PIN r0_rd_out[129]
    DIRECTION OUTPUT ;
    USE SIGNAL ;
    SHAPE ABUTMENT ;
    PORT
      LAYER met2 ;
      RECT 774.110 856.380 774.250 856.800 ;
    END
  END r0_rd_out[129]
  PIN rw0_addr_in[0]
    DIRECTION INPUT ;
    USE SIGNAL ;
    SHAPE ABUTMENT ;
    PORT
      LAYER met3 ;
      RECT 0.000 654.690 0.900 654.990 ;
    END
  END rw0_addr_in[0]
  PIN rw0_addr_in[1]
    DIRECTION INPUT ;
    USE SIGNAL ;
    SHAPE ABUTMENT ;
    PORT
      LAYER met3 ;
      RECT 0.000 674.410 0.900 674.710 ;
    END
  END rw0_addr_in[1]
  PIN rw0_addr_in[2]
    DIRECTION INPUT ;
    USE SIGNAL ;
    SHAPE ABUTMENT ;
    PORT
      LAYER met3 ;
      RECT 0.000 694.130 0.900 694.430 ;
    END
  END rw0_addr_in[2]
  PIN rw0_addr_in[3]
    DIRECTION INPUT ;
    USE SIGNAL ;
    SHAPE ABUTMENT ;
    PORT
      LAYER met3 ;
      RECT 0.000 713.850 0.900 714.150 ;
    END
  END rw0_addr_in[3]
  PIN rw0_addr_in[4]
    DIRECTION INPUT ;
    USE SIGNAL ;
    SHAPE ABUTMENT ;
    PORT
      LAYER met3 ;
      RECT 0.000 733.570 0.900 733.870 ;
    END
  END rw0_addr_in[4]
  PIN rw0_addr_in[5]
    DIRECTION INPUT ;
    USE SIGNAL ;
    SHAPE ABUTMENT ;
    PORT
      LAYER met3 ;
      RECT 861.140 634.970 862.040 635.270 ;
    END
  END rw0_addr_in[5]
  PIN rw0_addr_in[6]
    DIRECTION INPUT ;
    USE SIGNAL ;
    SHAPE ABUTMENT ;
    PORT
      LAYER met3 ;
      RECT 861.140 654.690 862.040 654.990 ;
    END
  END rw0_addr_in[6]
  PIN rw0_addr_in[7]
    DIRECTION INPUT ;
    USE SIGNAL ;
    SHAPE ABUTMENT ;
    PORT
      LAYER met3 ;
      RECT 861.140 674.410 862.040 674.710 ;
    END
  END rw0_addr_in[7]
  PIN rw0_addr_in[8]
    DIRECTION INPUT ;
    USE SIGNAL ;
    SHAPE ABUTMENT ;
    PORT
      LAYER met3 ;
      RECT 861.140 694.130 862.040 694.430 ;
    END
  END rw0_addr_in[8]
  PIN r0_addr_in[0]
    DIRECTION INPUT ;
    USE SIGNAL ;
    SHAPE ABUTMENT ;
    PORT
      LAYER met3 ;
      RECT 0.000 753.290 0.900 753.590 ;
    END
  END r0_addr_in[0]
  PIN r0_addr_in[1]
    DIRECTION INPUT ;
    USE SIGNAL ;
    SHAPE ABUTMENT ;
    PORT
      LAYER met3 ;
      RECT 0.000 773.010 0.900 773.310 ;
    END
  END r0_addr_in[1]
  PIN r0_addr_in[2]
    DIRECTION INPUT ;
    USE SIGNAL ;
    SHAPE ABUTMENT ;
    PORT
      LAYER met3 ;
      RECT 0.000 792.730 0.900 793.030 ;
    END
  END r0_addr_in[2]
  PIN r0_addr_in[3]
    DIRECTION INPUT ;
    USE SIGNAL ;
    SHAPE ABUTMENT ;
    PORT
      LAYER met3 ;
      RECT 0.000 812.450 0.900 812.750 ;
    END
  END r0_addr_in[3]
  PIN r0_addr_in[4]
    DIRECTION INPUT ;
    USE SIGNAL ;
    SHAPE ABUTMENT ;
    PORT
      LAYER met3 ;
      RECT 0.000 832.170 0.900 832.470 ;
    END
  END r0_addr_in[4]
  PIN r0_addr_in[5]
    DIRECTION INPUT ;
    USE SIGNAL ;
    SHAPE ABUTMENT ;
    PORT
      LAYER met3 ;
      RECT 861.140 713.850 862.040 714.150 ;
    END
  END r0_addr_in[5]
  PIN r0_addr_in[6]
    DIRECTION INPUT ;
    USE SIGNAL ;
    SHAPE ABUTMENT ;
    PORT
      LAYER met3 ;
      RECT 861.140 733.570 862.040 733.870 ;
    END
  END r0_addr_in[6]
  PIN r0_addr_in[7]
    DIRECTION INPUT ;
    USE SIGNAL ;
    SHAPE ABUTMENT ;
    PORT
      LAYER met3 ;
      RECT 861.140 753.290 862.040 753.590 ;
    END
  END r0_addr_in[7]
  PIN r0_addr_in[8]
    DIRECTION INPUT ;
    USE SIGNAL ;
    SHAPE ABUTMENT ;
    PORT
      LAYER met3 ;
      RECT 861.140 773.010 862.040 773.310 ;
    END
  END r0_addr_in[8]
  PIN rw0_we_in
    DIRECTION INPUT ;
    USE SIGNAL ;
    SHAPE ABUTMENT ;
    PORT
      LAYER met2 ;
      RECT 780.090 856.380 780.230 856.800 ;
    END
  END rw0_we_in
  PIN rw0_ce_in
    DIRECTION INPUT ;
    USE SIGNAL ;
    SHAPE ABUTMENT ;
    PORT
      LAYER met2 ;
      RECT 786.070 856.380 786.210 856.800 ;
    END
  END rw0_ce_in
  PIN rw0_clk
    DIRECTION INPUT ;
    USE SIGNAL ;
    SHAPE ABUTMENT ;
    PORT
      LAYER met2 ;
      RECT 792.050 856.380 792.190 856.800 ;
    END
  END rw0_clk
  PIN r0_ce_in
    DIRECTION INPUT ;
    USE SIGNAL ;
    SHAPE ABUTMENT ;
    PORT
      LAYER met2 ;
      RECT 798.030 856.380 798.170 856.800 ;
    END
  END r0_ce_in
  PIN r0_clk
    DIRECTION INPUT ;
    USE SIGNAL ;
    SHAPE ABUTMENT ;
    PORT
      LAYER met2 ;
      RECT 804.010 856.380 804.150 856.800 ;
    END
  END r0_clk
  PIN VSS
    DIRECTION INOUT ;
    USE GROUND ;
    PORT
      LAYER met4 ;
      RECT 2.160 4.080 3.360 852.720 ;
      RECT 13.040 4.080 14.240 852.720 ;
      RECT 23.920 4.080 25.120 852.720 ;
      RECT 34.800 4.080 36.000 852.720 ;
      RECT 45.680 4.080 46.880 852.720 ;
      RECT 56.560 4.080 57.760 852.720 ;
      RECT 67.440 4.080 68.640 852.720 ;
      RECT 78.320 4.080 79.520 852.720 ;
      RECT 89.200 4.080 90.400 852.720 ;
      RECT 100.080 4.080 101.280 852.720 ;
      RECT 110.960 4.080 112.160 852.720 ;
      RECT 121.840 4.080 123.040 852.720 ;
      RECT 132.720 4.080 133.920 852.720 ;
      RECT 143.600 4.080 144.800 852.720 ;
      RECT 154.480 4.080 155.680 852.720 ;
      RECT 165.360 4.080 166.560 852.720 ;
      RECT 176.240 4.080 177.440 852.720 ;
      RECT 187.120 4.080 188.320 852.720 ;
      RECT 198.000 4.080 199.200 852.720 ;
      RECT 208.880 4.080 210.080 852.720 ;
      RECT 219.760 4.080 220.960 852.720 ;
      RECT 230.640 4.080 231.840 852.720 ;
      RECT 241.520 4.080 242.720 852.720 ;
      RECT 252.400 4.080 253.600 852.720 ;
      RECT 263.280 4.080 264.480 852.720 ;
      RECT 274.160 4.080 275.360 852.720 ;
      RECT 285.040 4.080 286.240 852.720 ;
      RECT 295.920 4.080 297.120 852.720 ;
      RECT 306.800 4.080 308.000 852.720 ;
      RECT 317.680 4.080 318.880 852.720 ;
      RECT 328.560 4.080 329.760 852.720 ;
      RECT 339.440 4.080 340.640 852.720 ;
      RECT 350.320 4.080 351.520 852.720 ;
      RECT 361.200 4.080 362.400 852.720 ;
      RECT 372.080 4.080 373.280 852.720 ;
      RECT 382.960 4.080 384.160 852.720 ;
      RECT 393.840 4.080 395.040 852.720 ;
      RECT 404.720 4.080 405.920 852.720 ;
      RECT 415.600 4.080 416.800 852.720 ;
      RECT 426.480 4.080 427.680 852.720 ;
      RECT 437.360 4.080 438.560 852.720 ;
      RECT 448.240 4.080 449.440 852.720 ;
      RECT 459.120 4.080 460.320 852.720 ;
      RECT 470.000 4.080 471.200 852.720 ;
      RECT 480.880 4.080 482.080 852.720 ;
      RECT 491.760 4.080 492.960 852.720 ;
      RECT 502.640 4.080 503.840 852.720 ;
      RECT 513.520 4.080 514.720 852.720 ;
      RECT 524.400 4.080 525.600 852.720 ;
      RECT 535.280 4.080 536.480 852.720 ;
      RECT 546.160 4.080 547.360 852.720 ;
      RECT 557.040 4.080 558.240 852.720 ;
      RECT 567.920 4.080 569.120 852.720 ;
      RECT 578.800 4.080 580.000 852.720 ;
      RECT 589.680 4.080 590.880 852.720 ;
      RECT 600.560 4.080 601.760 852.720 ;
      RECT 611.440 4.080 612.640 852.720 ;
      RECT 622.320 4.080 623.520 852.720 ;
      RECT 633.200 4.080 634.400 852.720 ;
      RECT 644.080 4.080 645.280 852.720 ;
      RECT 654.960 4.080 656.160 852.720 ;
      RECT 665.840 4.080 667.040 852.720 ;
      RECT 676.720 4.080 677.920 852.720 ;
      RECT 687.600 4.080 688.800 852.720 ;
      RECT 698.480 4.080 699.680 852.720 ;
      RECT 709.360 4.080 710.560 852.720 ;
      RECT 720.240 4.080 721.440 852.720 ;
      RECT 731.120 4.080 732.320 852.720 ;
      RECT 742.000 4.080 743.200 852.720 ;
      RECT 752.880 4.080 754.080 852.720 ;
      RECT 763.760 4.080 764.960 852.720 ;
      RECT 774.640 4.080 775.840 852.720 ;
      RECT 785.520 4.080 786.720 852.720 ;
      RECT 796.400 4.080 797.600 852.720 ;
      RECT 807.280 4.080 808.480 852.720 ;
      RECT 818.160 4.080 819.360 852.720 ;
      RECT 829.040 4.080 830.240 852.720 ;
      RECT 839.920 4.080 841.120 852.720 ;
      RECT 850.800 4.080 852.000 852.720 ;
    END
  END VSS
  PIN VDD
    DIRECTION INOUT ;
    USE POWER ;
    PORT
      LAYER met4 ;
      RECT 2.160 4.080 3.360 852.720 ;
      RECT 13.040 4.080 14.240 852.720 ;
      RECT 23.920 4.080 25.120 852.720 ;
      RECT 34.800 4.080 36.000 852.720 ;
      RECT 45.680 4.080 46.880 852.720 ;
      RECT 56.560 4.080 57.760 852.720 ;
      RECT 67.440 4.080 68.640 852.720 ;
      RECT 78.320 4.080 79.520 852.720 ;
      RECT 89.200 4.080 90.400 852.720 ;
      RECT 100.080 4.080 101.280 852.720 ;
      RECT 110.960 4.080 112.160 852.720 ;
      RECT 121.840 4.080 123.040 852.720 ;
      RECT 132.720 4.080 133.920 852.720 ;
      RECT 143.600 4.080 144.800 852.720 ;
      RECT 154.480 4.080 155.680 852.720 ;
      RECT 165.360 4.080 166.560 852.720 ;
      RECT 176.240 4.080 177.440 852.720 ;
      RECT 187.120 4.080 188.320 852.720 ;
      RECT 198.000 4.080 199.200 852.720 ;
      RECT 208.880 4.080 210.080 852.720 ;
      RECT 219.760 4.080 220.960 852.720 ;
      RECT 230.640 4.080 231.840 852.720 ;
      RECT 241.520 4.080 242.720 852.720 ;
      RECT 252.400 4.080 253.600 852.720 ;
      RECT 263.280 4.080 264.480 852.720 ;
      RECT 274.160 4.080 275.360 852.720 ;
      RECT 285.040 4.080 286.240 852.720 ;
      RECT 295.920 4.080 297.120 852.720 ;
      RECT 306.800 4.080 308.000 852.720 ;
      RECT 317.680 4.080 318.880 852.720 ;
      RECT 328.560 4.080 329.760 852.720 ;
      RECT 339.440 4.080 340.640 852.720 ;
      RECT 350.320 4.080 351.520 852.720 ;
      RECT 361.200 4.080 362.400 852.720 ;
      RECT 372.080 4.080 373.280 852.720 ;
      RECT 382.960 4.080 384.160 852.720 ;
      RECT 393.840 4.080 395.040 852.720 ;
      RECT 404.720 4.080 405.920 852.720 ;
      RECT 415.600 4.080 416.800 852.720 ;
      RECT 426.480 4.080 427.680 852.720 ;
      RECT 437.360 4.080 438.560 852.720 ;
      RECT 448.240 4.080 449.440 852.720 ;
      RECT 459.120 4.080 460.320 852.720 ;
      RECT 470.000 4.080 471.200 852.720 ;
      RECT 480.880 4.080 482.080 852.720 ;
      RECT 491.760 4.080 492.960 852.720 ;
      RECT 502.640 4.080 503.840 852.720 ;
      RECT 513.520 4.080 514.720 852.720 ;
      RECT 524.400 4.080 525.600 852.720 ;
      RECT 535.280 4.080 536.480 852.720 ;
      RECT 546.160 4.080 547.360 852.720 ;
      RECT 557.040 4.080 558.240 852.720 ;
      RECT 567.920 4.080 569.120 852.720 ;
      RECT 578.800 4.080 580.000 852.720 ;
      RECT 589.680 4.080 590.880 852.720 ;
      RECT 600.560 4.080 601.760 852.720 ;
      RECT 611.440 4.080 612.640 852.720 ;
      RECT 622.320 4.080 623.520 852.720 ;
      RECT 633.200 4.080 634.400 852.720 ;
      RECT 644.080 4.080 645.280 852.720 ;
      RECT 654.960 4.080 656.160 852.720 ;
      RECT 665.840 4.080 667.040 852.720 ;
      RECT 676.720 4.080 677.920 852.720 ;
      RECT 687.600 4.080 688.800 852.720 ;
      RECT 698.480 4.080 699.680 852.720 ;
      RECT 709.360 4.080 710.560 852.720 ;
      RECT 720.240 4.080 721.440 852.720 ;
      RECT 731.120 4.080 732.320 852.720 ;
      RECT 742.000 4.080 743.200 852.720 ;
      RECT 752.880 4.080 754.080 852.720 ;
      RECT 763.760 4.080 764.960 852.720 ;
      RECT 774.640 4.080 775.840 852.720 ;
      RECT 785.520 4.080 786.720 852.720 ;
      RECT 796.400 4.080 797.600 852.720 ;
      RECT 807.280 4.080 808.480 852.720 ;
      RECT 818.160 4.080 819.360 852.720 ;
      RECT 829.040 4.080 830.240 852.720 ;
      RECT 839.920 4.080 841.120 852.720 ;
      RECT 850.800 4.080 852.000 852.720 ;
    END
  END VDD
  OBS
    LAYER met1 ;
    RECT 0 0 862.040 856.800 ;
    LAYER met2 ;
    RECT 0 0 862.040 856.800 ;
    LAYER met3 ;
    RECT 0 0 862.040 856.800 ;
    LAYER met4 ;
    RECT 0 0 862.040 856.800 ;
  END
END fakeram130_1rw1r_130w512d

END LIBRARY
